VERSION 5.8 ;
BUSBITCHARS "[]" ;
DIVIDERCHAR "/" ;
UNITS
    DATABASE MICRONS 1000 ;
END UNITS

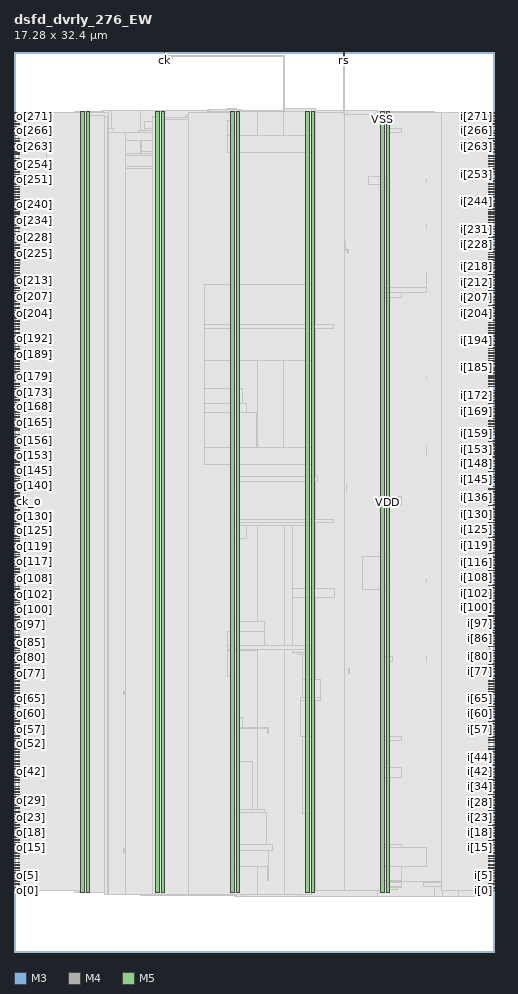
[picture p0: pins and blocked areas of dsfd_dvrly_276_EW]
MACRO dsfd_dvrly_276_EW
  FOREIGN dsfd_dvrly_276_EW 0 0 ;
  CLASS BLOCK ;
  SIZE 17.28 BY 32.4 ;
  PIN ck
    DIRECTION INPUT ;
    USE SIGNAL ;
    PORT
      LAYER M3 ;
        RECT  5.4 32.256 5.418 32.4 ;
    END
  END ck
  PIN ck_o
    DIRECTION OUTPUT ;
    USE SIGNAL ;
    PORT
      LAYER M4 ;
        RECT  0 16.224 0.192 16.248 ;
    END
  END ck_o
  PIN i[0]
    DIRECTION INPUT ;
    USE SIGNAL ;
    PORT
      LAYER M4 ;
        RECT  17.088 2.208 17.28 2.232 ;
    END
  END i[0]
  PIN i[100]
    DIRECTION INPUT ;
    USE SIGNAL ;
    PORT
      LAYER M4 ;
        RECT  17.088 12.384 17.28 12.408 ;
    END
  END i[100]
  PIN i[101]
    DIRECTION INPUT ;
    USE SIGNAL ;
    PORT
      LAYER M4 ;
        RECT  17.088 12.48 17.28 12.504 ;
    END
  END i[101]
  PIN i[102]
    DIRECTION INPUT ;
    USE SIGNAL ;
    PORT
      LAYER M4 ;
        RECT  17.088 12.624 17.28 12.648 ;
    END
  END i[102]
  PIN i[103]
    DIRECTION INPUT ;
    USE SIGNAL ;
    PORT
      LAYER M4 ;
        RECT  17.088 12.72 17.28 12.744 ;
    END
  END i[103]
  PIN i[104]
    DIRECTION INPUT ;
    USE SIGNAL ;
    PORT
      LAYER M4 ;
        RECT  17.088 12.816 17.28 12.84 ;
    END
  END i[104]
  PIN i[105]
    DIRECTION INPUT ;
    USE SIGNAL ;
    PORT
      LAYER M4 ;
        RECT  17.088 12.912 17.28 12.936 ;
    END
  END i[105]
  PIN i[106]
    DIRECTION INPUT ;
    USE SIGNAL ;
    PORT
      LAYER M4 ;
        RECT  17.088 13.008 17.28 13.032 ;
    END
  END i[106]
  PIN i[107]
    DIRECTION INPUT ;
    USE SIGNAL ;
    PORT
      LAYER M4 ;
        RECT  17.088 13.104 17.28 13.128 ;
    END
  END i[107]
  PIN i[108]
    DIRECTION INPUT ;
    USE SIGNAL ;
    PORT
      LAYER M4 ;
        RECT  17.088 13.2 17.28 13.224 ;
    END
  END i[108]
  PIN i[109]
    DIRECTION INPUT ;
    USE SIGNAL ;
    PORT
      LAYER M4 ;
        RECT  17.088 13.296 17.28 13.32 ;
    END
  END i[109]
  PIN i[10]
    DIRECTION INPUT ;
    USE SIGNAL ;
    PORT
      LAYER M4 ;
        RECT  17.088 3.264 17.28 3.288 ;
    END
  END i[10]
  PIN i[110]
    DIRECTION INPUT ;
    USE SIGNAL ;
    PORT
      LAYER M4 ;
        RECT  17.088 13.392 17.28 13.416 ;
    END
  END i[110]
  PIN i[111]
    DIRECTION INPUT ;
    USE SIGNAL ;
    PORT
      LAYER M4 ;
        RECT  17.088 13.536 17.28 13.56 ;
    END
  END i[111]
  PIN i[112]
    DIRECTION INPUT ;
    USE SIGNAL ;
    PORT
      LAYER M4 ;
        RECT  17.088 13.632 17.28 13.656 ;
    END
  END i[112]
  PIN i[113]
    DIRECTION INPUT ;
    USE SIGNAL ;
    PORT
      LAYER M4 ;
        RECT  17.088 13.728 17.28 13.752 ;
    END
  END i[113]
  PIN i[114]
    DIRECTION INPUT ;
    USE SIGNAL ;
    PORT
      LAYER M4 ;
        RECT  17.088 13.824 17.28 13.848 ;
    END
  END i[114]
  PIN i[115]
    DIRECTION INPUT ;
    USE SIGNAL ;
    PORT
      LAYER M4 ;
        RECT  17.088 13.92 17.28 13.944 ;
    END
  END i[115]
  PIN i[116]
    DIRECTION INPUT ;
    USE SIGNAL ;
    PORT
      LAYER M4 ;
        RECT  17.088 14.016 17.28 14.04 ;
    END
  END i[116]
  PIN i[117]
    DIRECTION INPUT ;
    USE SIGNAL ;
    PORT
      LAYER M4 ;
        RECT  17.088 14.112 17.28 14.136 ;
    END
  END i[117]
  PIN i[118]
    DIRECTION INPUT ;
    USE SIGNAL ;
    PORT
      LAYER M4 ;
        RECT  17.088 14.208 17.28 14.232 ;
    END
  END i[118]
  PIN i[119]
    DIRECTION INPUT ;
    USE SIGNAL ;
    PORT
      LAYER M4 ;
        RECT  17.088 14.352 17.28 14.376 ;
    END
  END i[119]
  PIN i[11]
    DIRECTION INPUT ;
    USE SIGNAL ;
    PORT
      LAYER M4 ;
        RECT  17.088 3.36 17.28 3.384 ;
    END
  END i[11]
  PIN i[120]
    DIRECTION INPUT ;
    USE SIGNAL ;
    PORT
      LAYER M4 ;
        RECT  17.088 14.448 17.28 14.472 ;
    END
  END i[120]
  PIN i[121]
    DIRECTION INPUT ;
    USE SIGNAL ;
    PORT
      LAYER M4 ;
        RECT  17.088 14.544 17.28 14.568 ;
    END
  END i[121]
  PIN i[122]
    DIRECTION INPUT ;
    USE SIGNAL ;
    PORT
      LAYER M4 ;
        RECT  17.088 14.64 17.28 14.664 ;
    END
  END i[122]
  PIN i[123]
    DIRECTION INPUT ;
    USE SIGNAL ;
    PORT
      LAYER M4 ;
        RECT  17.088 14.736 17.28 14.76 ;
    END
  END i[123]
  PIN i[124]
    DIRECTION INPUT ;
    USE SIGNAL ;
    PORT
      LAYER M4 ;
        RECT  17.088 14.832 17.28 14.856 ;
    END
  END i[124]
  PIN i[125]
    DIRECTION INPUT ;
    USE SIGNAL ;
    PORT
      LAYER M4 ;
        RECT  17.088 14.928 17.28 14.952 ;
    END
  END i[125]
  PIN i[126]
    DIRECTION INPUT ;
    USE SIGNAL ;
    PORT
      LAYER M4 ;
        RECT  17.088 15.024 17.28 15.048 ;
    END
  END i[126]
  PIN i[127]
    DIRECTION INPUT ;
    USE SIGNAL ;
    PORT
      LAYER M4 ;
        RECT  17.088 15.12 17.28 15.144 ;
    END
  END i[127]
  PIN i[128]
    DIRECTION INPUT ;
    USE SIGNAL ;
    PORT
      LAYER M4 ;
        RECT  17.088 15.264 17.28 15.288 ;
    END
  END i[128]
  PIN i[129]
    DIRECTION INPUT ;
    USE SIGNAL ;
    PORT
      LAYER M4 ;
        RECT  17.088 15.36 17.28 15.384 ;
    END
  END i[129]
  PIN i[12]
    DIRECTION INPUT ;
    USE SIGNAL ;
    PORT
      LAYER M4 ;
        RECT  17.088 3.456 17.28 3.48 ;
    END
  END i[12]
  PIN i[130]
    DIRECTION INPUT ;
    USE SIGNAL ;
    PORT
      LAYER M4 ;
        RECT  17.088 15.456 17.28 15.48 ;
    END
  END i[130]
  PIN i[131]
    DIRECTION INPUT ;
    USE SIGNAL ;
    PORT
      LAYER M4 ;
        RECT  17.088 15.552 17.28 15.576 ;
    END
  END i[131]
  PIN i[132]
    DIRECTION INPUT ;
    USE SIGNAL ;
    PORT
      LAYER M4 ;
        RECT  17.088 15.648 17.28 15.672 ;
    END
  END i[132]
  PIN i[133]
    DIRECTION INPUT ;
    USE SIGNAL ;
    PORT
      LAYER M4 ;
        RECT  17.088 15.744 17.28 15.768 ;
    END
  END i[133]
  PIN i[134]
    DIRECTION INPUT ;
    USE SIGNAL ;
    PORT
      LAYER M4 ;
        RECT  17.088 15.84 17.28 15.864 ;
    END
  END i[134]
  PIN i[135]
    DIRECTION INPUT ;
    USE SIGNAL ;
    PORT
      LAYER M4 ;
        RECT  17.088 15.936 17.28 15.96 ;
    END
  END i[135]
  PIN i[136]
    DIRECTION INPUT ;
    USE SIGNAL ;
    PORT
      LAYER M4 ;
        RECT  17.088 16.08 17.28 16.104 ;
    END
  END i[136]
  PIN i[137]
    DIRECTION INPUT ;
    USE SIGNAL ;
    PORT
      LAYER M4 ;
        RECT  17.088 16.176 17.28 16.2 ;
    END
  END i[137]
  PIN i[138]
    DIRECTION INPUT ;
    USE SIGNAL ;
    PORT
      LAYER M4 ;
        RECT  17.088 16.272 17.28 16.296 ;
    END
  END i[138]
  PIN i[139]
    DIRECTION INPUT ;
    USE SIGNAL ;
    PORT
      LAYER M4 ;
        RECT  17.088 16.368 17.28 16.392 ;
    END
  END i[139]
  PIN i[13]
    DIRECTION INPUT ;
    USE SIGNAL ;
    PORT
      LAYER M4 ;
        RECT  17.088 3.552 17.28 3.576 ;
    END
  END i[13]
  PIN i[140]
    DIRECTION INPUT ;
    USE SIGNAL ;
    PORT
      LAYER M4 ;
        RECT  17.088 16.464 17.28 16.488 ;
    END
  END i[140]
  PIN i[141]
    DIRECTION INPUT ;
    USE SIGNAL ;
    PORT
      LAYER M4 ;
        RECT  17.088 16.56 17.28 16.584 ;
    END
  END i[141]
  PIN i[142]
    DIRECTION INPUT ;
    USE SIGNAL ;
    PORT
      LAYER M4 ;
        RECT  17.088 16.656 17.28 16.68 ;
    END
  END i[142]
  PIN i[143]
    DIRECTION INPUT ;
    USE SIGNAL ;
    PORT
      LAYER M4 ;
        RECT  17.088 16.752 17.28 16.776 ;
    END
  END i[143]
  PIN i[144]
    DIRECTION INPUT ;
    USE SIGNAL ;
    PORT
      LAYER M4 ;
        RECT  17.088 16.896 17.28 16.92 ;
    END
  END i[144]
  PIN i[145]
    DIRECTION INPUT ;
    USE SIGNAL ;
    PORT
      LAYER M4 ;
        RECT  17.088 16.992 17.28 17.016 ;
    END
  END i[145]
  PIN i[146]
    DIRECTION INPUT ;
    USE SIGNAL ;
    PORT
      LAYER M4 ;
        RECT  17.088 17.088 17.28 17.112 ;
    END
  END i[146]
  PIN i[147]
    DIRECTION INPUT ;
    USE SIGNAL ;
    PORT
      LAYER M4 ;
        RECT  17.088 17.184 17.28 17.208 ;
    END
  END i[147]
  PIN i[148]
    DIRECTION INPUT ;
    USE SIGNAL ;
    PORT
      LAYER M4 ;
        RECT  17.088 17.28 17.28 17.304 ;
    END
  END i[148]
  PIN i[149]
    DIRECTION INPUT ;
    USE SIGNAL ;
    PORT
      LAYER M4 ;
        RECT  17.088 17.376 17.28 17.4 ;
    END
  END i[149]
  PIN i[14]
    DIRECTION INPUT ;
    USE SIGNAL ;
    PORT
      LAYER M4 ;
        RECT  17.088 3.648 17.28 3.672 ;
    END
  END i[14]
  PIN i[150]
    DIRECTION INPUT ;
    USE SIGNAL ;
    PORT
      LAYER M4 ;
        RECT  17.088 17.472 17.28 17.496 ;
    END
  END i[150]
  PIN i[151]
    DIRECTION INPUT ;
    USE SIGNAL ;
    PORT
      LAYER M4 ;
        RECT  17.088 17.568 17.28 17.592 ;
    END
  END i[151]
  PIN i[152]
    DIRECTION INPUT ;
    USE SIGNAL ;
    PORT
      LAYER M4 ;
        RECT  17.088 17.664 17.28 17.688 ;
    END
  END i[152]
  PIN i[153]
    DIRECTION INPUT ;
    USE SIGNAL ;
    PORT
      LAYER M4 ;
        RECT  17.088 17.808 17.28 17.832 ;
    END
  END i[153]
  PIN i[154]
    DIRECTION INPUT ;
    USE SIGNAL ;
    PORT
      LAYER M4 ;
        RECT  17.088 17.904 17.28 17.928 ;
    END
  END i[154]
  PIN i[155]
    DIRECTION INPUT ;
    USE SIGNAL ;
    PORT
      LAYER M4 ;
        RECT  17.088 18 17.28 18.024 ;
    END
  END i[155]
  PIN i[156]
    DIRECTION INPUT ;
    USE SIGNAL ;
    PORT
      LAYER M4 ;
        RECT  17.088 18.096 17.28 18.12 ;
    END
  END i[156]
  PIN i[157]
    DIRECTION INPUT ;
    USE SIGNAL ;
    PORT
      LAYER M4 ;
        RECT  17.088 18.192 17.28 18.216 ;
    END
  END i[157]
  PIN i[158]
    DIRECTION INPUT ;
    USE SIGNAL ;
    PORT
      LAYER M4 ;
        RECT  17.088 18.288 17.28 18.312 ;
    END
  END i[158]
  PIN i[159]
    DIRECTION INPUT ;
    USE SIGNAL ;
    PORT
      LAYER M4 ;
        RECT  17.088 18.384 17.28 18.408 ;
    END
  END i[159]
  PIN i[15]
    DIRECTION INPUT ;
    USE SIGNAL ;
    PORT
      LAYER M4 ;
        RECT  17.088 3.744 17.28 3.768 ;
    END
  END i[15]
  PIN i[160]
    DIRECTION INPUT ;
    USE SIGNAL ;
    PORT
      LAYER M4 ;
        RECT  17.088 18.48 17.28 18.504 ;
    END
  END i[160]
  PIN i[161]
    DIRECTION INPUT ;
    USE SIGNAL ;
    PORT
      LAYER M4 ;
        RECT  17.088 18.624 17.28 18.648 ;
    END
  END i[161]
  PIN i[162]
    DIRECTION INPUT ;
    USE SIGNAL ;
    PORT
      LAYER M4 ;
        RECT  17.088 18.72 17.28 18.744 ;
    END
  END i[162]
  PIN i[163]
    DIRECTION INPUT ;
    USE SIGNAL ;
    PORT
      LAYER M4 ;
        RECT  17.088 18.816 17.28 18.84 ;
    END
  END i[163]
  PIN i[164]
    DIRECTION INPUT ;
    USE SIGNAL ;
    PORT
      LAYER M4 ;
        RECT  17.088 18.912 17.28 18.936 ;
    END
  END i[164]
  PIN i[165]
    DIRECTION INPUT ;
    USE SIGNAL ;
    PORT
      LAYER M4 ;
        RECT  17.088 19.008 17.28 19.032 ;
    END
  END i[165]
  PIN i[166]
    DIRECTION INPUT ;
    USE SIGNAL ;
    PORT
      LAYER M4 ;
        RECT  17.088 19.104 17.28 19.128 ;
    END
  END i[166]
  PIN i[167]
    DIRECTION INPUT ;
    USE SIGNAL ;
    PORT
      LAYER M4 ;
        RECT  17.088 19.2 17.28 19.224 ;
    END
  END i[167]
  PIN i[168]
    DIRECTION INPUT ;
    USE SIGNAL ;
    PORT
      LAYER M4 ;
        RECT  17.088 19.296 17.28 19.32 ;
    END
  END i[168]
  PIN i[169]
    DIRECTION INPUT ;
    USE SIGNAL ;
    PORT
      LAYER M4 ;
        RECT  17.088 19.44 17.28 19.464 ;
    END
  END i[169]
  PIN i[16]
    DIRECTION INPUT ;
    USE SIGNAL ;
    PORT
      LAYER M4 ;
        RECT  17.088 3.84 17.28 3.864 ;
    END
  END i[16]
  PIN i[170]
    DIRECTION INPUT ;
    USE SIGNAL ;
    PORT
      LAYER M4 ;
        RECT  17.088 19.536 17.28 19.56 ;
    END
  END i[170]
  PIN i[171]
    DIRECTION INPUT ;
    USE SIGNAL ;
    PORT
      LAYER M4 ;
        RECT  17.088 19.632 17.28 19.656 ;
    END
  END i[171]
  PIN i[172]
    DIRECTION INPUT ;
    USE SIGNAL ;
    PORT
      LAYER M4 ;
        RECT  17.088 19.728 17.28 19.752 ;
    END
  END i[172]
  PIN i[173]
    DIRECTION INPUT ;
    USE SIGNAL ;
    PORT
      LAYER M4 ;
        RECT  17.088 19.824 17.28 19.848 ;
    END
  END i[173]
  PIN i[174]
    DIRECTION INPUT ;
    USE SIGNAL ;
    PORT
      LAYER M4 ;
        RECT  17.088 19.92 17.28 19.944 ;
    END
  END i[174]
  PIN i[175]
    DIRECTION INPUT ;
    USE SIGNAL ;
    PORT
      LAYER M4 ;
        RECT  17.088 20.016 17.28 20.04 ;
    END
  END i[175]
  PIN i[176]
    DIRECTION INPUT ;
    USE SIGNAL ;
    PORT
      LAYER M4 ;
        RECT  17.088 20.112 17.28 20.136 ;
    END
  END i[176]
  PIN i[177]
    DIRECTION INPUT ;
    USE SIGNAL ;
    PORT
      LAYER M4 ;
        RECT  17.088 20.208 17.28 20.232 ;
    END
  END i[177]
  PIN i[178]
    DIRECTION INPUT ;
    USE SIGNAL ;
    PORT
      LAYER M4 ;
        RECT  17.088 20.352 17.28 20.376 ;
    END
  END i[178]
  PIN i[179]
    DIRECTION INPUT ;
    USE SIGNAL ;
    PORT
      LAYER M4 ;
        RECT  17.088 20.448 17.28 20.472 ;
    END
  END i[179]
  PIN i[17]
    DIRECTION INPUT ;
    USE SIGNAL ;
    PORT
      LAYER M4 ;
        RECT  17.088 3.936 17.28 3.96 ;
    END
  END i[17]
  PIN i[180]
    DIRECTION INPUT ;
    USE SIGNAL ;
    PORT
      LAYER M4 ;
        RECT  17.088 20.544 17.28 20.568 ;
    END
  END i[180]
  PIN i[181]
    DIRECTION INPUT ;
    USE SIGNAL ;
    PORT
      LAYER M4 ;
        RECT  17.088 20.64 17.28 20.664 ;
    END
  END i[181]
  PIN i[182]
    DIRECTION INPUT ;
    USE SIGNAL ;
    PORT
      LAYER M4 ;
        RECT  17.088 20.736 17.28 20.76 ;
    END
  END i[182]
  PIN i[183]
    DIRECTION INPUT ;
    USE SIGNAL ;
    PORT
      LAYER M4 ;
        RECT  17.088 20.832 17.28 20.856 ;
    END
  END i[183]
  PIN i[184]
    DIRECTION INPUT ;
    USE SIGNAL ;
    PORT
      LAYER M4 ;
        RECT  17.088 20.928 17.28 20.952 ;
    END
  END i[184]
  PIN i[185]
    DIRECTION INPUT ;
    USE SIGNAL ;
    PORT
      LAYER M4 ;
        RECT  17.088 21.024 17.28 21.048 ;
    END
  END i[185]
  PIN i[186]
    DIRECTION INPUT ;
    USE SIGNAL ;
    PORT
      LAYER M4 ;
        RECT  17.088 21.168 17.28 21.192 ;
    END
  END i[186]
  PIN i[187]
    DIRECTION INPUT ;
    USE SIGNAL ;
    PORT
      LAYER M4 ;
        RECT  17.088 21.264 17.28 21.288 ;
    END
  END i[187]
  PIN i[188]
    DIRECTION INPUT ;
    USE SIGNAL ;
    PORT
      LAYER M4 ;
        RECT  17.088 21.36 17.28 21.384 ;
    END
  END i[188]
  PIN i[189]
    DIRECTION INPUT ;
    USE SIGNAL ;
    PORT
      LAYER M4 ;
        RECT  17.088 21.456 17.28 21.48 ;
    END
  END i[189]
  PIN i[18]
    DIRECTION INPUT ;
    USE SIGNAL ;
    PORT
      LAYER M4 ;
        RECT  17.088 4.032 17.28 4.056 ;
    END
  END i[18]
  PIN i[190]
    DIRECTION INPUT ;
    USE SIGNAL ;
    PORT
      LAYER M4 ;
        RECT  17.088 21.552 17.28 21.576 ;
    END
  END i[190]
  PIN i[191]
    DIRECTION INPUT ;
    USE SIGNAL ;
    PORT
      LAYER M4 ;
        RECT  17.088 21.648 17.28 21.672 ;
    END
  END i[191]
  PIN i[192]
    DIRECTION INPUT ;
    USE SIGNAL ;
    PORT
      LAYER M4 ;
        RECT  17.088 21.744 17.28 21.768 ;
    END
  END i[192]
  PIN i[193]
    DIRECTION INPUT ;
    USE SIGNAL ;
    PORT
      LAYER M4 ;
        RECT  17.088 21.84 17.28 21.864 ;
    END
  END i[193]
  PIN i[194]
    DIRECTION INPUT ;
    USE SIGNAL ;
    PORT
      LAYER M4 ;
        RECT  17.088 21.984 17.28 22.008 ;
    END
  END i[194]
  PIN i[195]
    DIRECTION INPUT ;
    USE SIGNAL ;
    PORT
      LAYER M4 ;
        RECT  17.088 22.08 17.28 22.104 ;
    END
  END i[195]
  PIN i[196]
    DIRECTION INPUT ;
    USE SIGNAL ;
    PORT
      LAYER M4 ;
        RECT  17.088 22.176 17.28 22.2 ;
    END
  END i[196]
  PIN i[197]
    DIRECTION INPUT ;
    USE SIGNAL ;
    PORT
      LAYER M4 ;
        RECT  17.088 22.272 17.28 22.296 ;
    END
  END i[197]
  PIN i[198]
    DIRECTION INPUT ;
    USE SIGNAL ;
    PORT
      LAYER M4 ;
        RECT  17.088 22.368 17.28 22.392 ;
    END
  END i[198]
  PIN i[199]
    DIRECTION INPUT ;
    USE SIGNAL ;
    PORT
      LAYER M4 ;
        RECT  17.088 22.464 17.28 22.488 ;
    END
  END i[199]
  PIN i[19]
    DIRECTION INPUT ;
    USE SIGNAL ;
    PORT
      LAYER M4 ;
        RECT  17.088 4.176 17.28 4.2 ;
    END
  END i[19]
  PIN i[1]
    DIRECTION INPUT ;
    USE SIGNAL ;
    PORT
      LAYER M4 ;
        RECT  17.088 2.304 17.28 2.328 ;
    END
  END i[1]
  PIN i[200]
    DIRECTION INPUT ;
    USE SIGNAL ;
    PORT
      LAYER M4 ;
        RECT  17.088 22.56 17.28 22.584 ;
    END
  END i[200]
  PIN i[201]
    DIRECTION INPUT ;
    USE SIGNAL ;
    PORT
      LAYER M4 ;
        RECT  17.088 22.656 17.28 22.68 ;
    END
  END i[201]
  PIN i[202]
    DIRECTION INPUT ;
    USE SIGNAL ;
    PORT
      LAYER M4 ;
        RECT  17.088 22.752 17.28 22.776 ;
    END
  END i[202]
  PIN i[203]
    DIRECTION INPUT ;
    USE SIGNAL ;
    PORT
      LAYER M4 ;
        RECT  17.088 22.896 17.28 22.92 ;
    END
  END i[203]
  PIN i[204]
    DIRECTION INPUT ;
    USE SIGNAL ;
    PORT
      LAYER M4 ;
        RECT  17.088 22.992 17.28 23.016 ;
    END
  END i[204]
  PIN i[205]
    DIRECTION INPUT ;
    USE SIGNAL ;
    PORT
      LAYER M4 ;
        RECT  17.088 23.088 17.28 23.112 ;
    END
  END i[205]
  PIN i[206]
    DIRECTION INPUT ;
    USE SIGNAL ;
    PORT
      LAYER M4 ;
        RECT  17.088 23.184 17.28 23.208 ;
    END
  END i[206]
  PIN i[207]
    DIRECTION INPUT ;
    USE SIGNAL ;
    PORT
      LAYER M4 ;
        RECT  17.088 23.28 17.28 23.304 ;
    END
  END i[207]
  PIN i[208]
    DIRECTION INPUT ;
    USE SIGNAL ;
    PORT
      LAYER M4 ;
        RECT  17.088 23.376 17.28 23.4 ;
    END
  END i[208]
  PIN i[209]
    DIRECTION INPUT ;
    USE SIGNAL ;
    PORT
      LAYER M4 ;
        RECT  17.088 23.472 17.28 23.496 ;
    END
  END i[209]
  PIN i[20]
    DIRECTION INPUT ;
    USE SIGNAL ;
    PORT
      LAYER M4 ;
        RECT  17.088 4.272 17.28 4.296 ;
    END
  END i[20]
  PIN i[210]
    DIRECTION INPUT ;
    USE SIGNAL ;
    PORT
      LAYER M4 ;
        RECT  17.088 23.568 17.28 23.592 ;
    END
  END i[210]
  PIN i[211]
    DIRECTION INPUT ;
    USE SIGNAL ;
    PORT
      LAYER M4 ;
        RECT  17.088 23.712 17.28 23.736 ;
    END
  END i[211]
  PIN i[212]
    DIRECTION INPUT ;
    USE SIGNAL ;
    PORT
      LAYER M4 ;
        RECT  17.088 23.808 17.28 23.832 ;
    END
  END i[212]
  PIN i[213]
    DIRECTION INPUT ;
    USE SIGNAL ;
    PORT
      LAYER M4 ;
        RECT  17.088 23.904 17.28 23.928 ;
    END
  END i[213]
  PIN i[214]
    DIRECTION INPUT ;
    USE SIGNAL ;
    PORT
      LAYER M4 ;
        RECT  17.088 24 17.28 24.024 ;
    END
  END i[214]
  PIN i[215]
    DIRECTION INPUT ;
    USE SIGNAL ;
    PORT
      LAYER M4 ;
        RECT  17.088 24.096 17.28 24.12 ;
    END
  END i[215]
  PIN i[216]
    DIRECTION INPUT ;
    USE SIGNAL ;
    PORT
      LAYER M4 ;
        RECT  17.088 24.192 17.28 24.216 ;
    END
  END i[216]
  PIN i[217]
    DIRECTION INPUT ;
    USE SIGNAL ;
    PORT
      LAYER M4 ;
        RECT  17.088 24.288 17.28 24.312 ;
    END
  END i[217]
  PIN i[218]
    DIRECTION INPUT ;
    USE SIGNAL ;
    PORT
      LAYER M4 ;
        RECT  17.088 24.384 17.28 24.408 ;
    END
  END i[218]
  PIN i[219]
    DIRECTION INPUT ;
    USE SIGNAL ;
    PORT
      LAYER M4 ;
        RECT  17.088 24.48 17.28 24.504 ;
    END
  END i[219]
  PIN i[21]
    DIRECTION INPUT ;
    USE SIGNAL ;
    PORT
      LAYER M4 ;
        RECT  17.088 4.368 17.28 4.392 ;
    END
  END i[21]
  PIN i[220]
    DIRECTION INPUT ;
    USE SIGNAL ;
    PORT
      LAYER M4 ;
        RECT  17.088 24.624 17.28 24.648 ;
    END
  END i[220]
  PIN i[221]
    DIRECTION INPUT ;
    USE SIGNAL ;
    PORT
      LAYER M4 ;
        RECT  17.088 24.72 17.28 24.744 ;
    END
  END i[221]
  PIN i[222]
    DIRECTION INPUT ;
    USE SIGNAL ;
    PORT
      LAYER M4 ;
        RECT  17.088 24.816 17.28 24.84 ;
    END
  END i[222]
  PIN i[223]
    DIRECTION INPUT ;
    USE SIGNAL ;
    PORT
      LAYER M4 ;
        RECT  17.088 24.912 17.28 24.936 ;
    END
  END i[223]
  PIN i[224]
    DIRECTION INPUT ;
    USE SIGNAL ;
    PORT
      LAYER M4 ;
        RECT  17.088 25.008 17.28 25.032 ;
    END
  END i[224]
  PIN i[225]
    DIRECTION INPUT ;
    USE SIGNAL ;
    PORT
      LAYER M4 ;
        RECT  17.088 25.104 17.28 25.128 ;
    END
  END i[225]
  PIN i[226]
    DIRECTION INPUT ;
    USE SIGNAL ;
    PORT
      LAYER M4 ;
        RECT  17.088 25.2 17.28 25.224 ;
    END
  END i[226]
  PIN i[227]
    DIRECTION INPUT ;
    USE SIGNAL ;
    PORT
      LAYER M4 ;
        RECT  17.088 25.296 17.28 25.32 ;
    END
  END i[227]
  PIN i[228]
    DIRECTION INPUT ;
    USE SIGNAL ;
    PORT
      LAYER M4 ;
        RECT  17.088 25.44 17.28 25.464 ;
    END
  END i[228]
  PIN i[229]
    DIRECTION INPUT ;
    USE SIGNAL ;
    PORT
      LAYER M4 ;
        RECT  17.088 25.536 17.28 25.56 ;
    END
  END i[229]
  PIN i[22]
    DIRECTION INPUT ;
    USE SIGNAL ;
    PORT
      LAYER M4 ;
        RECT  17.088 4.464 17.28 4.488 ;
    END
  END i[22]
  PIN i[230]
    DIRECTION INPUT ;
    USE SIGNAL ;
    PORT
      LAYER M4 ;
        RECT  17.088 25.632 17.28 25.656 ;
    END
  END i[230]
  PIN i[231]
    DIRECTION INPUT ;
    USE SIGNAL ;
    PORT
      LAYER M4 ;
        RECT  17.088 25.728 17.28 25.752 ;
    END
  END i[231]
  PIN i[232]
    DIRECTION INPUT ;
    USE SIGNAL ;
    PORT
      LAYER M4 ;
        RECT  17.088 25.824 17.28 25.848 ;
    END
  END i[232]
  PIN i[233]
    DIRECTION INPUT ;
    USE SIGNAL ;
    PORT
      LAYER M4 ;
        RECT  17.088 25.92 17.28 25.944 ;
    END
  END i[233]
  PIN i[234]
    DIRECTION INPUT ;
    USE SIGNAL ;
    PORT
      LAYER M4 ;
        RECT  17.088 26.016 17.28 26.04 ;
    END
  END i[234]
  PIN i[235]
    DIRECTION INPUT ;
    USE SIGNAL ;
    PORT
      LAYER M4 ;
        RECT  17.088 26.112 17.28 26.136 ;
    END
  END i[235]
  PIN i[236]
    DIRECTION INPUT ;
    USE SIGNAL ;
    PORT
      LAYER M4 ;
        RECT  17.088 26.256 17.28 26.28 ;
    END
  END i[236]
  PIN i[237]
    DIRECTION INPUT ;
    USE SIGNAL ;
    PORT
      LAYER M4 ;
        RECT  17.088 26.352 17.28 26.376 ;
    END
  END i[237]
  PIN i[238]
    DIRECTION INPUT ;
    USE SIGNAL ;
    PORT
      LAYER M4 ;
        RECT  17.088 26.448 17.28 26.472 ;
    END
  END i[238]
  PIN i[239]
    DIRECTION INPUT ;
    USE SIGNAL ;
    PORT
      LAYER M4 ;
        RECT  17.088 26.544 17.28 26.568 ;
    END
  END i[239]
  PIN i[23]
    DIRECTION INPUT ;
    USE SIGNAL ;
    PORT
      LAYER M4 ;
        RECT  17.088 4.56 17.28 4.584 ;
    END
  END i[23]
  PIN i[240]
    DIRECTION INPUT ;
    USE SIGNAL ;
    PORT
      LAYER M4 ;
        RECT  17.088 26.64 17.28 26.664 ;
    END
  END i[240]
  PIN i[241]
    DIRECTION INPUT ;
    USE SIGNAL ;
    PORT
      LAYER M4 ;
        RECT  17.088 26.736 17.28 26.76 ;
    END
  END i[241]
  PIN i[242]
    DIRECTION INPUT ;
    USE SIGNAL ;
    PORT
      LAYER M4 ;
        RECT  17.088 26.832 17.28 26.856 ;
    END
  END i[242]
  PIN i[243]
    DIRECTION INPUT ;
    USE SIGNAL ;
    PORT
      LAYER M4 ;
        RECT  17.088 26.928 17.28 26.952 ;
    END
  END i[243]
  PIN i[244]
    DIRECTION INPUT ;
    USE SIGNAL ;
    PORT
      LAYER M4 ;
        RECT  17.088 27.024 17.28 27.048 ;
    END
  END i[244]
  PIN i[245]
    DIRECTION INPUT ;
    USE SIGNAL ;
    PORT
      LAYER M4 ;
        RECT  17.088 27.168 17.28 27.192 ;
    END
  END i[245]
  PIN i[246]
    DIRECTION INPUT ;
    USE SIGNAL ;
    PORT
      LAYER M4 ;
        RECT  17.088 27.264 17.28 27.288 ;
    END
  END i[246]
  PIN i[247]
    DIRECTION INPUT ;
    USE SIGNAL ;
    PORT
      LAYER M4 ;
        RECT  17.088 27.36 17.28 27.384 ;
    END
  END i[247]
  PIN i[248]
    DIRECTION INPUT ;
    USE SIGNAL ;
    PORT
      LAYER M4 ;
        RECT  17.088 27.456 17.28 27.48 ;
    END
  END i[248]
  PIN i[249]
    DIRECTION INPUT ;
    USE SIGNAL ;
    PORT
      LAYER M4 ;
        RECT  17.088 27.552 17.28 27.576 ;
    END
  END i[249]
  PIN i[24]
    DIRECTION INPUT ;
    USE SIGNAL ;
    PORT
      LAYER M4 ;
        RECT  17.088 4.656 17.28 4.68 ;
    END
  END i[24]
  PIN i[250]
    DIRECTION INPUT ;
    USE SIGNAL ;
    PORT
      LAYER M4 ;
        RECT  17.088 27.648 17.28 27.672 ;
    END
  END i[250]
  PIN i[251]
    DIRECTION INPUT ;
    USE SIGNAL ;
    PORT
      LAYER M4 ;
        RECT  17.088 27.744 17.28 27.768 ;
    END
  END i[251]
  PIN i[252]
    DIRECTION INPUT ;
    USE SIGNAL ;
    PORT
      LAYER M4 ;
        RECT  17.088 27.84 17.28 27.864 ;
    END
  END i[252]
  PIN i[253]
    DIRECTION INPUT ;
    USE SIGNAL ;
    PORT
      LAYER M4 ;
        RECT  17.088 27.984 17.28 28.008 ;
    END
  END i[253]
  PIN i[254]
    DIRECTION INPUT ;
    USE SIGNAL ;
    PORT
      LAYER M4 ;
        RECT  17.088 28.08 17.28 28.104 ;
    END
  END i[254]
  PIN i[255]
    DIRECTION INPUT ;
    USE SIGNAL ;
    PORT
      LAYER M4 ;
        RECT  17.088 28.176 17.28 28.2 ;
    END
  END i[255]
  PIN i[256]
    DIRECTION INPUT ;
    USE SIGNAL ;
    PORT
      LAYER M4 ;
        RECT  17.088 28.272 17.28 28.296 ;
    END
  END i[256]
  PIN i[257]
    DIRECTION INPUT ;
    USE SIGNAL ;
    PORT
      LAYER M4 ;
        RECT  17.088 28.368 17.28 28.392 ;
    END
  END i[257]
  PIN i[258]
    DIRECTION INPUT ;
    USE SIGNAL ;
    PORT
      LAYER M4 ;
        RECT  17.088 28.464 17.28 28.488 ;
    END
  END i[258]
  PIN i[259]
    DIRECTION INPUT ;
    USE SIGNAL ;
    PORT
      LAYER M4 ;
        RECT  17.088 28.56 17.28 28.584 ;
    END
  END i[259]
  PIN i[25]
    DIRECTION INPUT ;
    USE SIGNAL ;
    PORT
      LAYER M4 ;
        RECT  17.088 4.752 17.28 4.776 ;
    END
  END i[25]
  PIN i[260]
    DIRECTION INPUT ;
    USE SIGNAL ;
    PORT
      LAYER M4 ;
        RECT  17.088 28.656 17.28 28.68 ;
    END
  END i[260]
  PIN i[261]
    DIRECTION INPUT ;
    USE SIGNAL ;
    PORT
      LAYER M4 ;
        RECT  17.088 28.8 17.28 28.824 ;
    END
  END i[261]
  PIN i[262]
    DIRECTION INPUT ;
    USE SIGNAL ;
    PORT
      LAYER M4 ;
        RECT  17.088 28.896 17.28 28.92 ;
    END
  END i[262]
  PIN i[263]
    DIRECTION INPUT ;
    USE SIGNAL ;
    PORT
      LAYER M4 ;
        RECT  17.088 28.992 17.28 29.016 ;
    END
  END i[263]
  PIN i[264]
    DIRECTION INPUT ;
    USE SIGNAL ;
    PORT
      LAYER M4 ;
        RECT  17.088 29.088 17.28 29.112 ;
    END
  END i[264]
  PIN i[265]
    DIRECTION INPUT ;
    USE SIGNAL ;
    PORT
      LAYER M4 ;
        RECT  17.088 29.184 17.28 29.208 ;
    END
  END i[265]
  PIN i[266]
    DIRECTION INPUT ;
    USE SIGNAL ;
    PORT
      LAYER M4 ;
        RECT  17.088 29.28 17.28 29.304 ;
    END
  END i[266]
  PIN i[267]
    DIRECTION INPUT ;
    USE SIGNAL ;
    PORT
      LAYER M4 ;
        RECT  17.088 29.376 17.28 29.4 ;
    END
  END i[267]
  PIN i[268]
    DIRECTION INPUT ;
    USE SIGNAL ;
    PORT
      LAYER M4 ;
        RECT  17.088 29.472 17.28 29.496 ;
    END
  END i[268]
  PIN i[269]
    DIRECTION INPUT ;
    USE SIGNAL ;
    PORT
      LAYER M4 ;
        RECT  17.088 29.568 17.28 29.592 ;
    END
  END i[269]
  PIN i[26]
    DIRECTION INPUT ;
    USE SIGNAL ;
    PORT
      LAYER M4 ;
        RECT  17.088 4.848 17.28 4.872 ;
    END
  END i[26]
  PIN i[270]
    DIRECTION INPUT ;
    USE SIGNAL ;
    PORT
      LAYER M4 ;
        RECT  17.088 29.712 17.28 29.736 ;
    END
  END i[270]
  PIN i[271]
    DIRECTION INPUT ;
    USE SIGNAL ;
    PORT
      LAYER M4 ;
        RECT  17.088 29.808 17.28 29.832 ;
    END
  END i[271]
  PIN i[272]
    DIRECTION INPUT ;
    USE SIGNAL ;
    PORT
      LAYER M4 ;
        RECT  17.088 29.904 17.28 29.928 ;
    END
  END i[272]
  PIN i[273]
    DIRECTION INPUT ;
    USE SIGNAL ;
    PORT
      LAYER M4 ;
        RECT  17.088 30 17.28 30.024 ;
    END
  END i[273]
  PIN i[274]
    DIRECTION INPUT ;
    USE SIGNAL ;
    PORT
      LAYER M4 ;
        RECT  17.088 30.096 17.28 30.12 ;
    END
  END i[274]
  PIN i[275]
    DIRECTION INPUT ;
    USE SIGNAL ;
    PORT
      LAYER M4 ;
        RECT  17.088 30.192 17.28 30.216 ;
    END
  END i[275]
  PIN i[27]
    DIRECTION INPUT ;
    USE SIGNAL ;
    PORT
      LAYER M4 ;
        RECT  17.088 4.992 17.28 5.016 ;
    END
  END i[27]
  PIN i[28]
    DIRECTION INPUT ;
    USE SIGNAL ;
    PORT
      LAYER M4 ;
        RECT  17.088 5.088 17.28 5.112 ;
    END
  END i[28]
  PIN i[29]
    DIRECTION INPUT ;
    USE SIGNAL ;
    PORT
      LAYER M4 ;
        RECT  17.088 5.184 17.28 5.208 ;
    END
  END i[29]
  PIN i[2]
    DIRECTION INPUT ;
    USE SIGNAL ;
    PORT
      LAYER M4 ;
        RECT  17.088 2.448 17.28 2.472 ;
    END
  END i[2]
  PIN i[30]
    DIRECTION INPUT ;
    USE SIGNAL ;
    PORT
      LAYER M4 ;
        RECT  17.088 5.28 17.28 5.304 ;
    END
  END i[30]
  PIN i[31]
    DIRECTION INPUT ;
    USE SIGNAL ;
    PORT
      LAYER M4 ;
        RECT  17.088 5.376 17.28 5.4 ;
    END
  END i[31]
  PIN i[32]
    DIRECTION INPUT ;
    USE SIGNAL ;
    PORT
      LAYER M4 ;
        RECT  17.088 5.472 17.28 5.496 ;
    END
  END i[32]
  PIN i[33]
    DIRECTION INPUT ;
    USE SIGNAL ;
    PORT
      LAYER M4 ;
        RECT  17.088 5.568 17.28 5.592 ;
    END
  END i[33]
  PIN i[34]
    DIRECTION INPUT ;
    USE SIGNAL ;
    PORT
      LAYER M4 ;
        RECT  17.088 5.664 17.28 5.688 ;
    END
  END i[34]
  PIN i[35]
    DIRECTION INPUT ;
    USE SIGNAL ;
    PORT
      LAYER M4 ;
        RECT  17.088 5.76 17.28 5.784 ;
    END
  END i[35]
  PIN i[36]
    DIRECTION INPUT ;
    USE SIGNAL ;
    PORT
      LAYER M4 ;
        RECT  17.088 5.904 17.28 5.928 ;
    END
  END i[36]
  PIN i[37]
    DIRECTION INPUT ;
    USE SIGNAL ;
    PORT
      LAYER M4 ;
        RECT  17.088 6 17.28 6.024 ;
    END
  END i[37]
  PIN i[38]
    DIRECTION INPUT ;
    USE SIGNAL ;
    PORT
      LAYER M4 ;
        RECT  17.088 6.096 17.28 6.12 ;
    END
  END i[38]
  PIN i[39]
    DIRECTION INPUT ;
    USE SIGNAL ;
    PORT
      LAYER M4 ;
        RECT  17.088 6.192 17.28 6.216 ;
    END
  END i[39]
  PIN i[3]
    DIRECTION INPUT ;
    USE SIGNAL ;
    PORT
      LAYER M4 ;
        RECT  17.088 2.544 17.28 2.568 ;
    END
  END i[3]
  PIN i[40]
    DIRECTION INPUT ;
    USE SIGNAL ;
    PORT
      LAYER M4 ;
        RECT  17.088 6.288 17.28 6.312 ;
    END
  END i[40]
  PIN i[41]
    DIRECTION INPUT ;
    USE SIGNAL ;
    PORT
      LAYER M4 ;
        RECT  17.088 6.384 17.28 6.408 ;
    END
  END i[41]
  PIN i[42]
    DIRECTION INPUT ;
    USE SIGNAL ;
    PORT
      LAYER M4 ;
        RECT  17.088 6.48 17.28 6.504 ;
    END
  END i[42]
  PIN i[43]
    DIRECTION INPUT ;
    USE SIGNAL ;
    PORT
      LAYER M4 ;
        RECT  17.088 6.576 17.28 6.6 ;
    END
  END i[43]
  PIN i[44]
    DIRECTION INPUT ;
    USE SIGNAL ;
    PORT
      LAYER M4 ;
        RECT  17.088 6.72 17.28 6.744 ;
    END
  END i[44]
  PIN i[45]
    DIRECTION INPUT ;
    USE SIGNAL ;
    PORT
      LAYER M4 ;
        RECT  17.088 6.816 17.28 6.84 ;
    END
  END i[45]
  PIN i[46]
    DIRECTION INPUT ;
    USE SIGNAL ;
    PORT
      LAYER M4 ;
        RECT  17.088 6.912 17.28 6.936 ;
    END
  END i[46]
  PIN i[47]
    DIRECTION INPUT ;
    USE SIGNAL ;
    PORT
      LAYER M4 ;
        RECT  17.088 7.008 17.28 7.032 ;
    END
  END i[47]
  PIN i[48]
    DIRECTION INPUT ;
    USE SIGNAL ;
    PORT
      LAYER M4 ;
        RECT  17.088 7.104 17.28 7.128 ;
    END
  END i[48]
  PIN i[49]
    DIRECTION INPUT ;
    USE SIGNAL ;
    PORT
      LAYER M4 ;
        RECT  17.088 7.2 17.28 7.224 ;
    END
  END i[49]
  PIN i[4]
    DIRECTION INPUT ;
    USE SIGNAL ;
    PORT
      LAYER M4 ;
        RECT  17.088 2.64 17.28 2.664 ;
    END
  END i[4]
  PIN i[50]
    DIRECTION INPUT ;
    USE SIGNAL ;
    PORT
      LAYER M4 ;
        RECT  17.088 7.296 17.28 7.32 ;
    END
  END i[50]
  PIN i[51]
    DIRECTION INPUT ;
    USE SIGNAL ;
    PORT
      LAYER M4 ;
        RECT  17.088 7.392 17.28 7.416 ;
    END
  END i[51]
  PIN i[52]
    DIRECTION INPUT ;
    USE SIGNAL ;
    PORT
      LAYER M4 ;
        RECT  17.088 7.536 17.28 7.56 ;
    END
  END i[52]
  PIN i[53]
    DIRECTION INPUT ;
    USE SIGNAL ;
    PORT
      LAYER M4 ;
        RECT  17.088 7.632 17.28 7.656 ;
    END
  END i[53]
  PIN i[54]
    DIRECTION INPUT ;
    USE SIGNAL ;
    PORT
      LAYER M4 ;
        RECT  17.088 7.728 17.28 7.752 ;
    END
  END i[54]
  PIN i[55]
    DIRECTION INPUT ;
    USE SIGNAL ;
    PORT
      LAYER M4 ;
        RECT  17.088 7.824 17.28 7.848 ;
    END
  END i[55]
  PIN i[56]
    DIRECTION INPUT ;
    USE SIGNAL ;
    PORT
      LAYER M4 ;
        RECT  17.088 7.92 17.28 7.944 ;
    END
  END i[56]
  PIN i[57]
    DIRECTION INPUT ;
    USE SIGNAL ;
    PORT
      LAYER M4 ;
        RECT  17.088 8.016 17.28 8.04 ;
    END
  END i[57]
  PIN i[58]
    DIRECTION INPUT ;
    USE SIGNAL ;
    PORT
      LAYER M4 ;
        RECT  17.088 8.112 17.28 8.136 ;
    END
  END i[58]
  PIN i[59]
    DIRECTION INPUT ;
    USE SIGNAL ;
    PORT
      LAYER M4 ;
        RECT  17.088 8.208 17.28 8.232 ;
    END
  END i[59]
  PIN i[5]
    DIRECTION INPUT ;
    USE SIGNAL ;
    PORT
      LAYER M4 ;
        RECT  17.088 2.736 17.28 2.76 ;
    END
  END i[5]
  PIN i[60]
    DIRECTION INPUT ;
    USE SIGNAL ;
    PORT
      LAYER M4 ;
        RECT  17.088 8.304 17.28 8.328 ;
    END
  END i[60]
  PIN i[61]
    DIRECTION INPUT ;
    USE SIGNAL ;
    PORT
      LAYER M4 ;
        RECT  17.088 8.448 17.28 8.472 ;
    END
  END i[61]
  PIN i[62]
    DIRECTION INPUT ;
    USE SIGNAL ;
    PORT
      LAYER M4 ;
        RECT  17.088 8.544 17.28 8.568 ;
    END
  END i[62]
  PIN i[63]
    DIRECTION INPUT ;
    USE SIGNAL ;
    PORT
      LAYER M4 ;
        RECT  17.088 8.64 17.28 8.664 ;
    END
  END i[63]
  PIN i[64]
    DIRECTION INPUT ;
    USE SIGNAL ;
    PORT
      LAYER M4 ;
        RECT  17.088 8.736 17.28 8.76 ;
    END
  END i[64]
  PIN i[65]
    DIRECTION INPUT ;
    USE SIGNAL ;
    PORT
      LAYER M4 ;
        RECT  17.088 8.832 17.28 8.856 ;
    END
  END i[65]
  PIN i[66]
    DIRECTION INPUT ;
    USE SIGNAL ;
    PORT
      LAYER M4 ;
        RECT  17.088 8.928 17.28 8.952 ;
    END
  END i[66]
  PIN i[67]
    DIRECTION INPUT ;
    USE SIGNAL ;
    PORT
      LAYER M4 ;
        RECT  17.088 9.024 17.28 9.048 ;
    END
  END i[67]
  PIN i[68]
    DIRECTION INPUT ;
    USE SIGNAL ;
    PORT
      LAYER M4 ;
        RECT  17.088 9.12 17.28 9.144 ;
    END
  END i[68]
  PIN i[69]
    DIRECTION INPUT ;
    USE SIGNAL ;
    PORT
      LAYER M4 ;
        RECT  17.088 9.264 17.28 9.288 ;
    END
  END i[69]
  PIN i[6]
    DIRECTION INPUT ;
    USE SIGNAL ;
    PORT
      LAYER M4 ;
        RECT  17.088 2.832 17.28 2.856 ;
    END
  END i[6]
  PIN i[70]
    DIRECTION INPUT ;
    USE SIGNAL ;
    PORT
      LAYER M4 ;
        RECT  17.088 9.36 17.28 9.384 ;
    END
  END i[70]
  PIN i[71]
    DIRECTION INPUT ;
    USE SIGNAL ;
    PORT
      LAYER M4 ;
        RECT  17.088 9.456 17.28 9.48 ;
    END
  END i[71]
  PIN i[72]
    DIRECTION INPUT ;
    USE SIGNAL ;
    PORT
      LAYER M4 ;
        RECT  17.088 9.552 17.28 9.576 ;
    END
  END i[72]
  PIN i[73]
    DIRECTION INPUT ;
    USE SIGNAL ;
    PORT
      LAYER M4 ;
        RECT  17.088 9.648 17.28 9.672 ;
    END
  END i[73]
  PIN i[74]
    DIRECTION INPUT ;
    USE SIGNAL ;
    PORT
      LAYER M4 ;
        RECT  17.088 9.744 17.28 9.768 ;
    END
  END i[74]
  PIN i[75]
    DIRECTION INPUT ;
    USE SIGNAL ;
    PORT
      LAYER M4 ;
        RECT  17.088 9.84 17.28 9.864 ;
    END
  END i[75]
  PIN i[76]
    DIRECTION INPUT ;
    USE SIGNAL ;
    PORT
      LAYER M4 ;
        RECT  17.088 9.936 17.28 9.96 ;
    END
  END i[76]
  PIN i[77]
    DIRECTION INPUT ;
    USE SIGNAL ;
    PORT
      LAYER M4 ;
        RECT  17.088 10.08 17.28 10.104 ;
    END
  END i[77]
  PIN i[78]
    DIRECTION INPUT ;
    USE SIGNAL ;
    PORT
      LAYER M4 ;
        RECT  17.088 10.176 17.28 10.2 ;
    END
  END i[78]
  PIN i[79]
    DIRECTION INPUT ;
    USE SIGNAL ;
    PORT
      LAYER M4 ;
        RECT  17.088 10.272 17.28 10.296 ;
    END
  END i[79]
  PIN i[7]
    DIRECTION INPUT ;
    USE SIGNAL ;
    PORT
      LAYER M4 ;
        RECT  17.088 2.928 17.28 2.952 ;
    END
  END i[7]
  PIN i[80]
    DIRECTION INPUT ;
    USE SIGNAL ;
    PORT
      LAYER M4 ;
        RECT  17.088 10.368 17.28 10.392 ;
    END
  END i[80]
  PIN i[81]
    DIRECTION INPUT ;
    USE SIGNAL ;
    PORT
      LAYER M4 ;
        RECT  17.088 10.464 17.28 10.488 ;
    END
  END i[81]
  PIN i[82]
    DIRECTION INPUT ;
    USE SIGNAL ;
    PORT
      LAYER M4 ;
        RECT  17.088 10.56 17.28 10.584 ;
    END
  END i[82]
  PIN i[83]
    DIRECTION INPUT ;
    USE SIGNAL ;
    PORT
      LAYER M4 ;
        RECT  17.088 10.656 17.28 10.68 ;
    END
  END i[83]
  PIN i[84]
    DIRECTION INPUT ;
    USE SIGNAL ;
    PORT
      LAYER M4 ;
        RECT  17.088 10.752 17.28 10.776 ;
    END
  END i[84]
  PIN i[85]
    DIRECTION INPUT ;
    USE SIGNAL ;
    PORT
      LAYER M4 ;
        RECT  17.088 10.848 17.28 10.872 ;
    END
  END i[85]
  PIN i[86]
    DIRECTION INPUT ;
    USE SIGNAL ;
    PORT
      LAYER M4 ;
        RECT  17.088 10.992 17.28 11.016 ;
    END
  END i[86]
  PIN i[87]
    DIRECTION INPUT ;
    USE SIGNAL ;
    PORT
      LAYER M4 ;
        RECT  17.088 11.088 17.28 11.112 ;
    END
  END i[87]
  PIN i[88]
    DIRECTION INPUT ;
    USE SIGNAL ;
    PORT
      LAYER M4 ;
        RECT  17.088 11.184 17.28 11.208 ;
    END
  END i[88]
  PIN i[89]
    DIRECTION INPUT ;
    USE SIGNAL ;
    PORT
      LAYER M4 ;
        RECT  17.088 11.28 17.28 11.304 ;
    END
  END i[89]
  PIN i[8]
    DIRECTION INPUT ;
    USE SIGNAL ;
    PORT
      LAYER M4 ;
        RECT  17.088 3.024 17.28 3.048 ;
    END
  END i[8]
  PIN i[90]
    DIRECTION INPUT ;
    USE SIGNAL ;
    PORT
      LAYER M4 ;
        RECT  17.088 11.376 17.28 11.4 ;
    END
  END i[90]
  PIN i[91]
    DIRECTION INPUT ;
    USE SIGNAL ;
    PORT
      LAYER M4 ;
        RECT  17.088 11.472 17.28 11.496 ;
    END
  END i[91]
  PIN i[92]
    DIRECTION INPUT ;
    USE SIGNAL ;
    PORT
      LAYER M4 ;
        RECT  17.088 11.568 17.28 11.592 ;
    END
  END i[92]
  PIN i[93]
    DIRECTION INPUT ;
    USE SIGNAL ;
    PORT
      LAYER M4 ;
        RECT  17.088 11.664 17.28 11.688 ;
    END
  END i[93]
  PIN i[94]
    DIRECTION INPUT ;
    USE SIGNAL ;
    PORT
      LAYER M4 ;
        RECT  17.088 11.808 17.28 11.832 ;
    END
  END i[94]
  PIN i[95]
    DIRECTION INPUT ;
    USE SIGNAL ;
    PORT
      LAYER M4 ;
        RECT  17.088 11.904 17.28 11.928 ;
    END
  END i[95]
  PIN i[96]
    DIRECTION INPUT ;
    USE SIGNAL ;
    PORT
      LAYER M4 ;
        RECT  17.088 12 17.28 12.024 ;
    END
  END i[96]
  PIN i[97]
    DIRECTION INPUT ;
    USE SIGNAL ;
    PORT
      LAYER M4 ;
        RECT  17.088 12.096 17.28 12.12 ;
    END
  END i[97]
  PIN i[98]
    DIRECTION INPUT ;
    USE SIGNAL ;
    PORT
      LAYER M4 ;
        RECT  17.088 12.192 17.28 12.216 ;
    END
  END i[98]
  PIN i[99]
    DIRECTION INPUT ;
    USE SIGNAL ;
    PORT
      LAYER M4 ;
        RECT  17.088 12.288 17.28 12.312 ;
    END
  END i[99]
  PIN i[9]
    DIRECTION INPUT ;
    USE SIGNAL ;
    PORT
      LAYER M4 ;
        RECT  17.088 3.12 17.28 3.144 ;
    END
  END i[9]
  PIN o[0]
    DIRECTION OUTPUT ;
    USE SIGNAL ;
    PORT
      LAYER M4 ;
        RECT  0 2.208 0.192 2.232 ;
    END
  END o[0]
  PIN o[100]
    DIRECTION OUTPUT ;
    USE SIGNAL ;
    PORT
      LAYER M4 ;
        RECT  0 12.336 0.192 12.36 ;
    END
  END o[100]
  PIN o[101]
    DIRECTION OUTPUT ;
    USE SIGNAL ;
    PORT
      LAYER M4 ;
        RECT  0 12.48 0.192 12.504 ;
    END
  END o[101]
  PIN o[102]
    DIRECTION OUTPUT ;
    USE SIGNAL ;
    PORT
      LAYER M4 ;
        RECT  0 12.576 0.192 12.6 ;
    END
  END o[102]
  PIN o[103]
    DIRECTION OUTPUT ;
    USE SIGNAL ;
    PORT
      LAYER M4 ;
        RECT  0 12.672 0.192 12.696 ;
    END
  END o[103]
  PIN o[104]
    DIRECTION OUTPUT ;
    USE SIGNAL ;
    PORT
      LAYER M4 ;
        RECT  0 12.768 0.192 12.792 ;
    END
  END o[104]
  PIN o[105]
    DIRECTION OUTPUT ;
    USE SIGNAL ;
    PORT
      LAYER M4 ;
        RECT  0 12.864 0.192 12.888 ;
    END
  END o[105]
  PIN o[106]
    DIRECTION OUTPUT ;
    USE SIGNAL ;
    PORT
      LAYER M4 ;
        RECT  0 12.96 0.192 12.984 ;
    END
  END o[106]
  PIN o[107]
    DIRECTION OUTPUT ;
    USE SIGNAL ;
    PORT
      LAYER M4 ;
        RECT  0 13.056 0.192 13.08 ;
    END
  END o[107]
  PIN o[108]
    DIRECTION OUTPUT ;
    USE SIGNAL ;
    PORT
      LAYER M4 ;
        RECT  0 13.152 0.192 13.176 ;
    END
  END o[108]
  PIN o[109]
    DIRECTION OUTPUT ;
    USE SIGNAL ;
    PORT
      LAYER M4 ;
        RECT  0 13.296 0.192 13.32 ;
    END
  END o[109]
  PIN o[10]
    DIRECTION OUTPUT ;
    USE SIGNAL ;
    PORT
      LAYER M4 ;
        RECT  0 3.216 0.192 3.24 ;
    END
  END o[10]
  PIN o[110]
    DIRECTION OUTPUT ;
    USE SIGNAL ;
    PORT
      LAYER M4 ;
        RECT  0 13.392 0.192 13.416 ;
    END
  END o[110]
  PIN o[111]
    DIRECTION OUTPUT ;
    USE SIGNAL ;
    PORT
      LAYER M4 ;
        RECT  0 13.488 0.192 13.512 ;
    END
  END o[111]
  PIN o[112]
    DIRECTION OUTPUT ;
    USE SIGNAL ;
    PORT
      LAYER M4 ;
        RECT  0 13.584 0.192 13.608 ;
    END
  END o[112]
  PIN o[113]
    DIRECTION OUTPUT ;
    USE SIGNAL ;
    PORT
      LAYER M4 ;
        RECT  0 13.68 0.192 13.704 ;
    END
  END o[113]
  PIN o[114]
    DIRECTION OUTPUT ;
    USE SIGNAL ;
    PORT
      LAYER M4 ;
        RECT  0 13.776 0.192 13.8 ;
    END
  END o[114]
  PIN o[115]
    DIRECTION OUTPUT ;
    USE SIGNAL ;
    PORT
      LAYER M4 ;
        RECT  0 13.872 0.192 13.896 ;
    END
  END o[115]
  PIN o[116]
    DIRECTION OUTPUT ;
    USE SIGNAL ;
    PORT
      LAYER M4 ;
        RECT  0 13.968 0.192 13.992 ;
    END
  END o[116]
  PIN o[117]
    DIRECTION OUTPUT ;
    USE SIGNAL ;
    PORT
      LAYER M4 ;
        RECT  0 14.064 0.192 14.088 ;
    END
  END o[117]
  PIN o[118]
    DIRECTION OUTPUT ;
    USE SIGNAL ;
    PORT
      LAYER M4 ;
        RECT  0 14.208 0.192 14.232 ;
    END
  END o[118]
  PIN o[119]
    DIRECTION OUTPUT ;
    USE SIGNAL ;
    PORT
      LAYER M4 ;
        RECT  0 14.304 0.192 14.328 ;
    END
  END o[119]
  PIN o[11]
    DIRECTION OUTPUT ;
    USE SIGNAL ;
    PORT
      LAYER M4 ;
        RECT  0 3.36 0.192 3.384 ;
    END
  END o[11]
  PIN o[120]
    DIRECTION OUTPUT ;
    USE SIGNAL ;
    PORT
      LAYER M4 ;
        RECT  0 14.4 0.192 14.424 ;
    END
  END o[120]
  PIN o[121]
    DIRECTION OUTPUT ;
    USE SIGNAL ;
    PORT
      LAYER M4 ;
        RECT  0 14.496 0.192 14.52 ;
    END
  END o[121]
  PIN o[122]
    DIRECTION OUTPUT ;
    USE SIGNAL ;
    PORT
      LAYER M4 ;
        RECT  0 14.592 0.192 14.616 ;
    END
  END o[122]
  PIN o[123]
    DIRECTION OUTPUT ;
    USE SIGNAL ;
    PORT
      LAYER M4 ;
        RECT  0 14.688 0.192 14.712 ;
    END
  END o[123]
  PIN o[124]
    DIRECTION OUTPUT ;
    USE SIGNAL ;
    PORT
      LAYER M4 ;
        RECT  0 14.784 0.192 14.808 ;
    END
  END o[124]
  PIN o[125]
    DIRECTION OUTPUT ;
    USE SIGNAL ;
    PORT
      LAYER M4 ;
        RECT  0 14.88 0.192 14.904 ;
    END
  END o[125]
  PIN o[126]
    DIRECTION OUTPUT ;
    USE SIGNAL ;
    PORT
      LAYER M4 ;
        RECT  0 14.976 0.192 15 ;
    END
  END o[126]
  PIN o[127]
    DIRECTION OUTPUT ;
    USE SIGNAL ;
    PORT
      LAYER M4 ;
        RECT  0 15.12 0.192 15.144 ;
    END
  END o[127]
  PIN o[128]
    DIRECTION OUTPUT ;
    USE SIGNAL ;
    PORT
      LAYER M4 ;
        RECT  0 15.216 0.192 15.24 ;
    END
  END o[128]
  PIN o[129]
    DIRECTION OUTPUT ;
    USE SIGNAL ;
    PORT
      LAYER M4 ;
        RECT  0 15.312 0.192 15.336 ;
    END
  END o[129]
  PIN o[12]
    DIRECTION OUTPUT ;
    USE SIGNAL ;
    PORT
      LAYER M4 ;
        RECT  0 3.456 0.192 3.48 ;
    END
  END o[12]
  PIN o[130]
    DIRECTION OUTPUT ;
    USE SIGNAL ;
    PORT
      LAYER M4 ;
        RECT  0 15.408 0.192 15.432 ;
    END
  END o[130]
  PIN o[131]
    DIRECTION OUTPUT ;
    USE SIGNAL ;
    PORT
      LAYER M4 ;
        RECT  0 15.504 0.192 15.528 ;
    END
  END o[131]
  PIN o[132]
    DIRECTION OUTPUT ;
    USE SIGNAL ;
    PORT
      LAYER M4 ;
        RECT  0 15.6 0.192 15.624 ;
    END
  END o[132]
  PIN o[133]
    DIRECTION OUTPUT ;
    USE SIGNAL ;
    PORT
      LAYER M4 ;
        RECT  0 15.696 0.192 15.72 ;
    END
  END o[133]
  PIN o[134]
    DIRECTION OUTPUT ;
    USE SIGNAL ;
    PORT
      LAYER M4 ;
        RECT  0 15.792 0.192 15.816 ;
    END
  END o[134]
  PIN o[135]
    DIRECTION OUTPUT ;
    USE SIGNAL ;
    PORT
      LAYER M4 ;
        RECT  0 15.888 0.192 15.912 ;
    END
  END o[135]
  PIN o[136]
    DIRECTION OUTPUT ;
    USE SIGNAL ;
    PORT
      LAYER M4 ;
        RECT  0 16.032 0.192 16.056 ;
    END
  END o[136]
  PIN o[137]
    DIRECTION OUTPUT ;
    USE SIGNAL ;
    PORT
      LAYER M4 ;
        RECT  0 16.128 0.192 16.152 ;
    END
  END o[137]
  PIN o[138]
    DIRECTION OUTPUT ;
    USE SIGNAL ;
    PORT
      LAYER M4 ;
        RECT  0 16.32 0.192 16.344 ;
    END
  END o[138]
  PIN o[139]
    DIRECTION OUTPUT ;
    USE SIGNAL ;
    PORT
      LAYER M4 ;
        RECT  0 16.416 0.192 16.44 ;
    END
  END o[139]
  PIN o[13]
    DIRECTION OUTPUT ;
    USE SIGNAL ;
    PORT
      LAYER M4 ;
        RECT  0 3.552 0.192 3.576 ;
    END
  END o[13]
  PIN o[140]
    DIRECTION OUTPUT ;
    USE SIGNAL ;
    PORT
      LAYER M4 ;
        RECT  0 16.512 0.192 16.536 ;
    END
  END o[140]
  PIN o[141]
    DIRECTION OUTPUT ;
    USE SIGNAL ;
    PORT
      LAYER M4 ;
        RECT  0 16.608 0.192 16.632 ;
    END
  END o[141]
  PIN o[142]
    DIRECTION OUTPUT ;
    USE SIGNAL ;
    PORT
      LAYER M4 ;
        RECT  0 16.704 0.192 16.728 ;
    END
  END o[142]
  PIN o[143]
    DIRECTION OUTPUT ;
    USE SIGNAL ;
    PORT
      LAYER M4 ;
        RECT  0 16.8 0.192 16.824 ;
    END
  END o[143]
  PIN o[144]
    DIRECTION OUTPUT ;
    USE SIGNAL ;
    PORT
      LAYER M4 ;
        RECT  0 16.944 0.192 16.968 ;
    END
  END o[144]
  PIN o[145]
    DIRECTION OUTPUT ;
    USE SIGNAL ;
    PORT
      LAYER M4 ;
        RECT  0 17.04 0.192 17.064 ;
    END
  END o[145]
  PIN o[146]
    DIRECTION OUTPUT ;
    USE SIGNAL ;
    PORT
      LAYER M4 ;
        RECT  0 17.136 0.192 17.16 ;
    END
  END o[146]
  PIN o[147]
    DIRECTION OUTPUT ;
    USE SIGNAL ;
    PORT
      LAYER M4 ;
        RECT  0 17.232 0.192 17.256 ;
    END
  END o[147]
  PIN o[148]
    DIRECTION OUTPUT ;
    USE SIGNAL ;
    PORT
      LAYER M4 ;
        RECT  0 17.328 0.192 17.352 ;
    END
  END o[148]
  PIN o[149]
    DIRECTION OUTPUT ;
    USE SIGNAL ;
    PORT
      LAYER M4 ;
        RECT  0 17.424 0.192 17.448 ;
    END
  END o[149]
  PIN o[14]
    DIRECTION OUTPUT ;
    USE SIGNAL ;
    PORT
      LAYER M4 ;
        RECT  0 3.648 0.192 3.672 ;
    END
  END o[14]
  PIN o[150]
    DIRECTION OUTPUT ;
    USE SIGNAL ;
    PORT
      LAYER M4 ;
        RECT  0 17.52 0.192 17.544 ;
    END
  END o[150]
  PIN o[151]
    DIRECTION OUTPUT ;
    USE SIGNAL ;
    PORT
      LAYER M4 ;
        RECT  0 17.616 0.192 17.64 ;
    END
  END o[151]
  PIN o[152]
    DIRECTION OUTPUT ;
    USE SIGNAL ;
    PORT
      LAYER M4 ;
        RECT  0 17.712 0.192 17.736 ;
    END
  END o[152]
  PIN o[153]
    DIRECTION OUTPUT ;
    USE SIGNAL ;
    PORT
      LAYER M4 ;
        RECT  0 17.856 0.192 17.88 ;
    END
  END o[153]
  PIN o[154]
    DIRECTION OUTPUT ;
    USE SIGNAL ;
    PORT
      LAYER M4 ;
        RECT  0 17.952 0.192 17.976 ;
    END
  END o[154]
  PIN o[155]
    DIRECTION OUTPUT ;
    USE SIGNAL ;
    PORT
      LAYER M4 ;
        RECT  0 18.048 0.192 18.072 ;
    END
  END o[155]
  PIN o[156]
    DIRECTION OUTPUT ;
    USE SIGNAL ;
    PORT
      LAYER M4 ;
        RECT  0 18.144 0.192 18.168 ;
    END
  END o[156]
  PIN o[157]
    DIRECTION OUTPUT ;
    USE SIGNAL ;
    PORT
      LAYER M4 ;
        RECT  0 18.24 0.192 18.264 ;
    END
  END o[157]
  PIN o[158]
    DIRECTION OUTPUT ;
    USE SIGNAL ;
    PORT
      LAYER M4 ;
        RECT  0 18.336 0.192 18.36 ;
    END
  END o[158]
  PIN o[159]
    DIRECTION OUTPUT ;
    USE SIGNAL ;
    PORT
      LAYER M4 ;
        RECT  0 18.432 0.192 18.456 ;
    END
  END o[159]
  PIN o[15]
    DIRECTION OUTPUT ;
    USE SIGNAL ;
    PORT
      LAYER M4 ;
        RECT  0 3.744 0.192 3.768 ;
    END
  END o[15]
  PIN o[160]
    DIRECTION OUTPUT ;
    USE SIGNAL ;
    PORT
      LAYER M4 ;
        RECT  0 18.528 0.192 18.552 ;
    END
  END o[160]
  PIN o[161]
    DIRECTION OUTPUT ;
    USE SIGNAL ;
    PORT
      LAYER M4 ;
        RECT  0 18.624 0.192 18.648 ;
    END
  END o[161]
  PIN o[162]
    DIRECTION OUTPUT ;
    USE SIGNAL ;
    PORT
      LAYER M4 ;
        RECT  0 18.768 0.192 18.792 ;
    END
  END o[162]
  PIN o[163]
    DIRECTION OUTPUT ;
    USE SIGNAL ;
    PORT
      LAYER M4 ;
        RECT  0 18.864 0.192 18.888 ;
    END
  END o[163]
  PIN o[164]
    DIRECTION OUTPUT ;
    USE SIGNAL ;
    PORT
      LAYER M4 ;
        RECT  0 18.96 0.192 18.984 ;
    END
  END o[164]
  PIN o[165]
    DIRECTION OUTPUT ;
    USE SIGNAL ;
    PORT
      LAYER M4 ;
        RECT  0 19.056 0.192 19.08 ;
    END
  END o[165]
  PIN o[166]
    DIRECTION OUTPUT ;
    USE SIGNAL ;
    PORT
      LAYER M4 ;
        RECT  0 19.152 0.192 19.176 ;
    END
  END o[166]
  PIN o[167]
    DIRECTION OUTPUT ;
    USE SIGNAL ;
    PORT
      LAYER M4 ;
        RECT  0 19.248 0.192 19.272 ;
    END
  END o[167]
  PIN o[168]
    DIRECTION OUTPUT ;
    USE SIGNAL ;
    PORT
      LAYER M4 ;
        RECT  0 19.344 0.192 19.368 ;
    END
  END o[168]
  PIN o[169]
    DIRECTION OUTPUT ;
    USE SIGNAL ;
    PORT
      LAYER M4 ;
        RECT  0 19.44 0.192 19.464 ;
    END
  END o[169]
  PIN o[16]
    DIRECTION OUTPUT ;
    USE SIGNAL ;
    PORT
      LAYER M4 ;
        RECT  0 3.84 0.192 3.864 ;
    END
  END o[16]
  PIN o[170]
    DIRECTION OUTPUT ;
    USE SIGNAL ;
    PORT
      LAYER M4 ;
        RECT  0 19.536 0.192 19.56 ;
    END
  END o[170]
  PIN o[171]
    DIRECTION OUTPUT ;
    USE SIGNAL ;
    PORT
      LAYER M4 ;
        RECT  0 19.68 0.192 19.704 ;
    END
  END o[171]
  PIN o[172]
    DIRECTION OUTPUT ;
    USE SIGNAL ;
    PORT
      LAYER M4 ;
        RECT  0 19.776 0.192 19.8 ;
    END
  END o[172]
  PIN o[173]
    DIRECTION OUTPUT ;
    USE SIGNAL ;
    PORT
      LAYER M4 ;
        RECT  0 19.872 0.192 19.896 ;
    END
  END o[173]
  PIN o[174]
    DIRECTION OUTPUT ;
    USE SIGNAL ;
    PORT
      LAYER M4 ;
        RECT  0 19.968 0.192 19.992 ;
    END
  END o[174]
  PIN o[175]
    DIRECTION OUTPUT ;
    USE SIGNAL ;
    PORT
      LAYER M4 ;
        RECT  0 20.064 0.192 20.088 ;
    END
  END o[175]
  PIN o[176]
    DIRECTION OUTPUT ;
    USE SIGNAL ;
    PORT
      LAYER M4 ;
        RECT  0 20.16 0.192 20.184 ;
    END
  END o[176]
  PIN o[177]
    DIRECTION OUTPUT ;
    USE SIGNAL ;
    PORT
      LAYER M4 ;
        RECT  0 20.256 0.192 20.28 ;
    END
  END o[177]
  PIN o[178]
    DIRECTION OUTPUT ;
    USE SIGNAL ;
    PORT
      LAYER M4 ;
        RECT  0 20.352 0.192 20.376 ;
    END
  END o[178]
  PIN o[179]
    DIRECTION OUTPUT ;
    USE SIGNAL ;
    PORT
      LAYER M4 ;
        RECT  0 20.448 0.192 20.472 ;
    END
  END o[179]
  PIN o[17]
    DIRECTION OUTPUT ;
    USE SIGNAL ;
    PORT
      LAYER M4 ;
        RECT  0 3.936 0.192 3.96 ;
    END
  END o[17]
  PIN o[180]
    DIRECTION OUTPUT ;
    USE SIGNAL ;
    PORT
      LAYER M4 ;
        RECT  0 20.592 0.192 20.616 ;
    END
  END o[180]
  PIN o[181]
    DIRECTION OUTPUT ;
    USE SIGNAL ;
    PORT
      LAYER M4 ;
        RECT  0 20.688 0.192 20.712 ;
    END
  END o[181]
  PIN o[182]
    DIRECTION OUTPUT ;
    USE SIGNAL ;
    PORT
      LAYER M4 ;
        RECT  0 20.784 0.192 20.808 ;
    END
  END o[182]
  PIN o[183]
    DIRECTION OUTPUT ;
    USE SIGNAL ;
    PORT
      LAYER M4 ;
        RECT  0 20.88 0.192 20.904 ;
    END
  END o[183]
  PIN o[184]
    DIRECTION OUTPUT ;
    USE SIGNAL ;
    PORT
      LAYER M4 ;
        RECT  0 20.976 0.192 21 ;
    END
  END o[184]
  PIN o[185]
    DIRECTION OUTPUT ;
    USE SIGNAL ;
    PORT
      LAYER M4 ;
        RECT  0 21.072 0.192 21.096 ;
    END
  END o[185]
  PIN o[186]
    DIRECTION OUTPUT ;
    USE SIGNAL ;
    PORT
      LAYER M4 ;
        RECT  0 21.168 0.192 21.192 ;
    END
  END o[186]
  PIN o[187]
    DIRECTION OUTPUT ;
    USE SIGNAL ;
    PORT
      LAYER M4 ;
        RECT  0 21.264 0.192 21.288 ;
    END
  END o[187]
  PIN o[188]
    DIRECTION OUTPUT ;
    USE SIGNAL ;
    PORT
      LAYER M4 ;
        RECT  0 21.36 0.192 21.384 ;
    END
  END o[188]
  PIN o[189]
    DIRECTION OUTPUT ;
    USE SIGNAL ;
    PORT
      LAYER M4 ;
        RECT  0 21.504 0.192 21.528 ;
    END
  END o[189]
  PIN o[18]
    DIRECTION OUTPUT ;
    USE SIGNAL ;
    PORT
      LAYER M4 ;
        RECT  0 4.032 0.192 4.056 ;
    END
  END o[18]
  PIN o[190]
    DIRECTION OUTPUT ;
    USE SIGNAL ;
    PORT
      LAYER M4 ;
        RECT  0 21.6 0.192 21.624 ;
    END
  END o[190]
  PIN o[191]
    DIRECTION OUTPUT ;
    USE SIGNAL ;
    PORT
      LAYER M4 ;
        RECT  0 21.696 0.192 21.72 ;
    END
  END o[191]
  PIN o[192]
    DIRECTION OUTPUT ;
    USE SIGNAL ;
    PORT
      LAYER M4 ;
        RECT  0 21.792 0.192 21.816 ;
    END
  END o[192]
  PIN o[193]
    DIRECTION OUTPUT ;
    USE SIGNAL ;
    PORT
      LAYER M4 ;
        RECT  0 21.888 0.192 21.912 ;
    END
  END o[193]
  PIN o[194]
    DIRECTION OUTPUT ;
    USE SIGNAL ;
    PORT
      LAYER M4 ;
        RECT  0 21.984 0.192 22.008 ;
    END
  END o[194]
  PIN o[195]
    DIRECTION OUTPUT ;
    USE SIGNAL ;
    PORT
      LAYER M4 ;
        RECT  0 22.08 0.192 22.104 ;
    END
  END o[195]
  PIN o[196]
    DIRECTION OUTPUT ;
    USE SIGNAL ;
    PORT
      LAYER M4 ;
        RECT  0 22.176 0.192 22.2 ;
    END
  END o[196]
  PIN o[197]
    DIRECTION OUTPUT ;
    USE SIGNAL ;
    PORT
      LAYER M4 ;
        RECT  0 22.272 0.192 22.296 ;
    END
  END o[197]
  PIN o[198]
    DIRECTION OUTPUT ;
    USE SIGNAL ;
    PORT
      LAYER M4 ;
        RECT  0 22.416 0.192 22.44 ;
    END
  END o[198]
  PIN o[199]
    DIRECTION OUTPUT ;
    USE SIGNAL ;
    PORT
      LAYER M4 ;
        RECT  0 22.512 0.192 22.536 ;
    END
  END o[199]
  PIN o[19]
    DIRECTION OUTPUT ;
    USE SIGNAL ;
    PORT
      LAYER M4 ;
        RECT  0 4.128 0.192 4.152 ;
    END
  END o[19]
  PIN o[1]
    DIRECTION OUTPUT ;
    USE SIGNAL ;
    PORT
      LAYER M4 ;
        RECT  0 2.304 0.192 2.328 ;
    END
  END o[1]
  PIN o[200]
    DIRECTION OUTPUT ;
    USE SIGNAL ;
    PORT
      LAYER M4 ;
        RECT  0 22.608 0.192 22.632 ;
    END
  END o[200]
  PIN o[201]
    DIRECTION OUTPUT ;
    USE SIGNAL ;
    PORT
      LAYER M4 ;
        RECT  0 22.704 0.192 22.728 ;
    END
  END o[201]
  PIN o[202]
    DIRECTION OUTPUT ;
    USE SIGNAL ;
    PORT
      LAYER M4 ;
        RECT  0 22.8 0.192 22.824 ;
    END
  END o[202]
  PIN o[203]
    DIRECTION OUTPUT ;
    USE SIGNAL ;
    PORT
      LAYER M4 ;
        RECT  0 22.896 0.192 22.92 ;
    END
  END o[203]
  PIN o[204]
    DIRECTION OUTPUT ;
    USE SIGNAL ;
    PORT
      LAYER M4 ;
        RECT  0 22.992 0.192 23.016 ;
    END
  END o[204]
  PIN o[205]
    DIRECTION OUTPUT ;
    USE SIGNAL ;
    PORT
      LAYER M4 ;
        RECT  0 23.088 0.192 23.112 ;
    END
  END o[205]
  PIN o[206]
    DIRECTION OUTPUT ;
    USE SIGNAL ;
    PORT
      LAYER M4 ;
        RECT  0 23.184 0.192 23.208 ;
    END
  END o[206]
  PIN o[207]
    DIRECTION OUTPUT ;
    USE SIGNAL ;
    PORT
      LAYER M4 ;
        RECT  0 23.328 0.192 23.352 ;
    END
  END o[207]
  PIN o[208]
    DIRECTION OUTPUT ;
    USE SIGNAL ;
    PORT
      LAYER M4 ;
        RECT  0 23.424 0.192 23.448 ;
    END
  END o[208]
  PIN o[209]
    DIRECTION OUTPUT ;
    USE SIGNAL ;
    PORT
      LAYER M4 ;
        RECT  0 23.52 0.192 23.544 ;
    END
  END o[209]
  PIN o[20]
    DIRECTION OUTPUT ;
    USE SIGNAL ;
    PORT
      LAYER M4 ;
        RECT  0 4.272 0.192 4.296 ;
    END
  END o[20]
  PIN o[210]
    DIRECTION OUTPUT ;
    USE SIGNAL ;
    PORT
      LAYER M4 ;
        RECT  0 23.616 0.192 23.64 ;
    END
  END o[210]
  PIN o[211]
    DIRECTION OUTPUT ;
    USE SIGNAL ;
    PORT
      LAYER M4 ;
        RECT  0 23.712 0.192 23.736 ;
    END
  END o[211]
  PIN o[212]
    DIRECTION OUTPUT ;
    USE SIGNAL ;
    PORT
      LAYER M4 ;
        RECT  0 23.808 0.192 23.832 ;
    END
  END o[212]
  PIN o[213]
    DIRECTION OUTPUT ;
    USE SIGNAL ;
    PORT
      LAYER M4 ;
        RECT  0 23.904 0.192 23.928 ;
    END
  END o[213]
  PIN o[214]
    DIRECTION OUTPUT ;
    USE SIGNAL ;
    PORT
      LAYER M4 ;
        RECT  0 24 0.192 24.024 ;
    END
  END o[214]
  PIN o[215]
    DIRECTION OUTPUT ;
    USE SIGNAL ;
    PORT
      LAYER M4 ;
        RECT  0 24.096 0.192 24.12 ;
    END
  END o[215]
  PIN o[216]
    DIRECTION OUTPUT ;
    USE SIGNAL ;
    PORT
      LAYER M4 ;
        RECT  0 24.24 0.192 24.264 ;
    END
  END o[216]
  PIN o[217]
    DIRECTION OUTPUT ;
    USE SIGNAL ;
    PORT
      LAYER M4 ;
        RECT  0 24.336 0.192 24.36 ;
    END
  END o[217]
  PIN o[218]
    DIRECTION OUTPUT ;
    USE SIGNAL ;
    PORT
      LAYER M4 ;
        RECT  0 24.432 0.192 24.456 ;
    END
  END o[218]
  PIN o[219]
    DIRECTION OUTPUT ;
    USE SIGNAL ;
    PORT
      LAYER M4 ;
        RECT  0 24.528 0.192 24.552 ;
    END
  END o[219]
  PIN o[21]
    DIRECTION OUTPUT ;
    USE SIGNAL ;
    PORT
      LAYER M4 ;
        RECT  0 4.368 0.192 4.392 ;
    END
  END o[21]
  PIN o[220]
    DIRECTION OUTPUT ;
    USE SIGNAL ;
    PORT
      LAYER M4 ;
        RECT  0 24.624 0.192 24.648 ;
    END
  END o[220]
  PIN o[221]
    DIRECTION OUTPUT ;
    USE SIGNAL ;
    PORT
      LAYER M4 ;
        RECT  0 24.72 0.192 24.744 ;
    END
  END o[221]
  PIN o[222]
    DIRECTION OUTPUT ;
    USE SIGNAL ;
    PORT
      LAYER M4 ;
        RECT  0 24.816 0.192 24.84 ;
    END
  END o[222]
  PIN o[223]
    DIRECTION OUTPUT ;
    USE SIGNAL ;
    PORT
      LAYER M4 ;
        RECT  0 24.912 0.192 24.936 ;
    END
  END o[223]
  PIN o[224]
    DIRECTION OUTPUT ;
    USE SIGNAL ;
    PORT
      LAYER M4 ;
        RECT  0 25.008 0.192 25.032 ;
    END
  END o[224]
  PIN o[225]
    DIRECTION OUTPUT ;
    USE SIGNAL ;
    PORT
      LAYER M4 ;
        RECT  0 25.152 0.192 25.176 ;
    END
  END o[225]
  PIN o[226]
    DIRECTION OUTPUT ;
    USE SIGNAL ;
    PORT
      LAYER M4 ;
        RECT  0 25.248 0.192 25.272 ;
    END
  END o[226]
  PIN o[227]
    DIRECTION OUTPUT ;
    USE SIGNAL ;
    PORT
      LAYER M4 ;
        RECT  0 25.344 0.192 25.368 ;
    END
  END o[227]
  PIN o[228]
    DIRECTION OUTPUT ;
    USE SIGNAL ;
    PORT
      LAYER M4 ;
        RECT  0 25.44 0.192 25.464 ;
    END
  END o[228]
  PIN o[229]
    DIRECTION OUTPUT ;
    USE SIGNAL ;
    PORT
      LAYER M4 ;
        RECT  0 25.536 0.192 25.56 ;
    END
  END o[229]
  PIN o[22]
    DIRECTION OUTPUT ;
    USE SIGNAL ;
    PORT
      LAYER M4 ;
        RECT  0 4.464 0.192 4.488 ;
    END
  END o[22]
  PIN o[230]
    DIRECTION OUTPUT ;
    USE SIGNAL ;
    PORT
      LAYER M4 ;
        RECT  0 25.632 0.192 25.656 ;
    END
  END o[230]
  PIN o[231]
    DIRECTION OUTPUT ;
    USE SIGNAL ;
    PORT
      LAYER M4 ;
        RECT  0 25.728 0.192 25.752 ;
    END
  END o[231]
  PIN o[232]
    DIRECTION OUTPUT ;
    USE SIGNAL ;
    PORT
      LAYER M4 ;
        RECT  0 25.824 0.192 25.848 ;
    END
  END o[232]
  PIN o[233]
    DIRECTION OUTPUT ;
    USE SIGNAL ;
    PORT
      LAYER M4 ;
        RECT  0 25.92 0.192 25.944 ;
    END
  END o[233]
  PIN o[234]
    DIRECTION OUTPUT ;
    USE SIGNAL ;
    PORT
      LAYER M4 ;
        RECT  0 26.064 0.192 26.088 ;
    END
  END o[234]
  PIN o[235]
    DIRECTION OUTPUT ;
    USE SIGNAL ;
    PORT
      LAYER M4 ;
        RECT  0 26.16 0.192 26.184 ;
    END
  END o[235]
  PIN o[236]
    DIRECTION OUTPUT ;
    USE SIGNAL ;
    PORT
      LAYER M4 ;
        RECT  0 26.256 0.192 26.28 ;
    END
  END o[236]
  PIN o[237]
    DIRECTION OUTPUT ;
    USE SIGNAL ;
    PORT
      LAYER M4 ;
        RECT  0 26.352 0.192 26.376 ;
    END
  END o[237]
  PIN o[238]
    DIRECTION OUTPUT ;
    USE SIGNAL ;
    PORT
      LAYER M4 ;
        RECT  0 26.448 0.192 26.472 ;
    END
  END o[238]
  PIN o[239]
    DIRECTION OUTPUT ;
    USE SIGNAL ;
    PORT
      LAYER M4 ;
        RECT  0 26.544 0.192 26.568 ;
    END
  END o[239]
  PIN o[23]
    DIRECTION OUTPUT ;
    USE SIGNAL ;
    PORT
      LAYER M4 ;
        RECT  0 4.56 0.192 4.584 ;
    END
  END o[23]
  PIN o[240]
    DIRECTION OUTPUT ;
    USE SIGNAL ;
    PORT
      LAYER M4 ;
        RECT  0 26.64 0.192 26.664 ;
    END
  END o[240]
  PIN o[241]
    DIRECTION OUTPUT ;
    USE SIGNAL ;
    PORT
      LAYER M4 ;
        RECT  0 26.736 0.192 26.76 ;
    END
  END o[241]
  PIN o[242]
    DIRECTION OUTPUT ;
    USE SIGNAL ;
    PORT
      LAYER M4 ;
        RECT  0 26.88 0.192 26.904 ;
    END
  END o[242]
  PIN o[243]
    DIRECTION OUTPUT ;
    USE SIGNAL ;
    PORT
      LAYER M4 ;
        RECT  0 26.976 0.192 27 ;
    END
  END o[243]
  PIN o[244]
    DIRECTION OUTPUT ;
    USE SIGNAL ;
    PORT
      LAYER M4 ;
        RECT  0 27.072 0.192 27.096 ;
    END
  END o[244]
  PIN o[245]
    DIRECTION OUTPUT ;
    USE SIGNAL ;
    PORT
      LAYER M4 ;
        RECT  0 27.168 0.192 27.192 ;
    END
  END o[245]
  PIN o[246]
    DIRECTION OUTPUT ;
    USE SIGNAL ;
    PORT
      LAYER M4 ;
        RECT  0 27.264 0.192 27.288 ;
    END
  END o[246]
  PIN o[247]
    DIRECTION OUTPUT ;
    USE SIGNAL ;
    PORT
      LAYER M4 ;
        RECT  0 27.36 0.192 27.384 ;
    END
  END o[247]
  PIN o[248]
    DIRECTION OUTPUT ;
    USE SIGNAL ;
    PORT
      LAYER M4 ;
        RECT  0 27.456 0.192 27.48 ;
    END
  END o[248]
  PIN o[249]
    DIRECTION OUTPUT ;
    USE SIGNAL ;
    PORT
      LAYER M4 ;
        RECT  0 27.552 0.192 27.576 ;
    END
  END o[249]
  PIN o[24]
    DIRECTION OUTPUT ;
    USE SIGNAL ;
    PORT
      LAYER M4 ;
        RECT  0 4.656 0.192 4.68 ;
    END
  END o[24]
  PIN o[250]
    DIRECTION OUTPUT ;
    USE SIGNAL ;
    PORT
      LAYER M4 ;
        RECT  0 27.648 0.192 27.672 ;
    END
  END o[250]
  PIN o[251]
    DIRECTION OUTPUT ;
    USE SIGNAL ;
    PORT
      LAYER M4 ;
        RECT  0 27.792 0.192 27.816 ;
    END
  END o[251]
  PIN o[252]
    DIRECTION OUTPUT ;
    USE SIGNAL ;
    PORT
      LAYER M4 ;
        RECT  0 27.888 0.192 27.912 ;
    END
  END o[252]
  PIN o[253]
    DIRECTION OUTPUT ;
    USE SIGNAL ;
    PORT
      LAYER M4 ;
        RECT  0 27.984 0.192 28.008 ;
    END
  END o[253]
  PIN o[254]
    DIRECTION OUTPUT ;
    USE SIGNAL ;
    PORT
      LAYER M4 ;
        RECT  0 28.08 0.192 28.104 ;
    END
  END o[254]
  PIN o[255]
    DIRECTION OUTPUT ;
    USE SIGNAL ;
    PORT
      LAYER M4 ;
        RECT  0 28.176 0.192 28.2 ;
    END
  END o[255]
  PIN o[256]
    DIRECTION OUTPUT ;
    USE SIGNAL ;
    PORT
      LAYER M4 ;
        RECT  0 28.272 0.192 28.296 ;
    END
  END o[256]
  PIN o[257]
    DIRECTION OUTPUT ;
    USE SIGNAL ;
    PORT
      LAYER M4 ;
        RECT  0 28.368 0.192 28.392 ;
    END
  END o[257]
  PIN o[258]
    DIRECTION OUTPUT ;
    USE SIGNAL ;
    PORT
      LAYER M4 ;
        RECT  0 28.464 0.192 28.488 ;
    END
  END o[258]
  PIN o[259]
    DIRECTION OUTPUT ;
    USE SIGNAL ;
    PORT
      LAYER M4 ;
        RECT  0 28.56 0.192 28.584 ;
    END
  END o[259]
  PIN o[25]
    DIRECTION OUTPUT ;
    USE SIGNAL ;
    PORT
      LAYER M4 ;
        RECT  0 4.752 0.192 4.776 ;
    END
  END o[25]
  PIN o[260]
    DIRECTION OUTPUT ;
    USE SIGNAL ;
    PORT
      LAYER M4 ;
        RECT  0 28.704 0.192 28.728 ;
    END
  END o[260]
  PIN o[261]
    DIRECTION OUTPUT ;
    USE SIGNAL ;
    PORT
      LAYER M4 ;
        RECT  0 28.8 0.192 28.824 ;
    END
  END o[261]
  PIN o[262]
    DIRECTION OUTPUT ;
    USE SIGNAL ;
    PORT
      LAYER M4 ;
        RECT  0 28.896 0.192 28.92 ;
    END
  END o[262]
  PIN o[263]
    DIRECTION OUTPUT ;
    USE SIGNAL ;
    PORT
      LAYER M4 ;
        RECT  0 28.992 0.192 29.016 ;
    END
  END o[263]
  PIN o[264]
    DIRECTION OUTPUT ;
    USE SIGNAL ;
    PORT
      LAYER M4 ;
        RECT  0 29.088 0.192 29.112 ;
    END
  END o[264]
  PIN o[265]
    DIRECTION OUTPUT ;
    USE SIGNAL ;
    PORT
      LAYER M4 ;
        RECT  0 29.184 0.192 29.208 ;
    END
  END o[265]
  PIN o[266]
    DIRECTION OUTPUT ;
    USE SIGNAL ;
    PORT
      LAYER M4 ;
        RECT  0 29.28 0.192 29.304 ;
    END
  END o[266]
  PIN o[267]
    DIRECTION OUTPUT ;
    USE SIGNAL ;
    PORT
      LAYER M4 ;
        RECT  0 29.376 0.192 29.4 ;
    END
  END o[267]
  PIN o[268]
    DIRECTION OUTPUT ;
    USE SIGNAL ;
    PORT
      LAYER M4 ;
        RECT  0 29.472 0.192 29.496 ;
    END
  END o[268]
  PIN o[269]
    DIRECTION OUTPUT ;
    USE SIGNAL ;
    PORT
      LAYER M4 ;
        RECT  0 29.616 0.192 29.64 ;
    END
  END o[269]
  PIN o[26]
    DIRECTION OUTPUT ;
    USE SIGNAL ;
    PORT
      LAYER M4 ;
        RECT  0 4.848 0.192 4.872 ;
    END
  END o[26]
  PIN o[270]
    DIRECTION OUTPUT ;
    USE SIGNAL ;
    PORT
      LAYER M4 ;
        RECT  0 29.712 0.192 29.736 ;
    END
  END o[270]
  PIN o[271]
    DIRECTION OUTPUT ;
    USE SIGNAL ;
    PORT
      LAYER M4 ;
        RECT  0 29.808 0.192 29.832 ;
    END
  END o[271]
  PIN o[272]
    DIRECTION OUTPUT ;
    USE SIGNAL ;
    PORT
      LAYER M4 ;
        RECT  0 29.904 0.192 29.928 ;
    END
  END o[272]
  PIN o[273]
    DIRECTION OUTPUT ;
    USE SIGNAL ;
    PORT
      LAYER M4 ;
        RECT  0 30 0.192 30.024 ;
    END
  END o[273]
  PIN o[274]
    DIRECTION OUTPUT ;
    USE SIGNAL ;
    PORT
      LAYER M4 ;
        RECT  0 30.096 0.192 30.12 ;
    END
  END o[274]
  PIN o[275]
    DIRECTION OUTPUT ;
    USE SIGNAL ;
    PORT
      LAYER M4 ;
        RECT  0 30.192 0.192 30.216 ;
    END
  END o[275]
  PIN o[27]
    DIRECTION OUTPUT ;
    USE SIGNAL ;
    PORT
      LAYER M4 ;
        RECT  0 4.944 0.192 4.968 ;
    END
  END o[27]
  PIN o[28]
    DIRECTION OUTPUT ;
    USE SIGNAL ;
    PORT
      LAYER M4 ;
        RECT  0 5.04 0.192 5.064 ;
    END
  END o[28]
  PIN o[29]
    DIRECTION OUTPUT ;
    USE SIGNAL ;
    PORT
      LAYER M4 ;
        RECT  0 5.184 0.192 5.208 ;
    END
  END o[29]
  PIN o[2]
    DIRECTION OUTPUT ;
    USE SIGNAL ;
    PORT
      LAYER M4 ;
        RECT  0 2.448 0.192 2.472 ;
    END
  END o[2]
  PIN o[30]
    DIRECTION OUTPUT ;
    USE SIGNAL ;
    PORT
      LAYER M4 ;
        RECT  0 5.28 0.192 5.304 ;
    END
  END o[30]
  PIN o[31]
    DIRECTION OUTPUT ;
    USE SIGNAL ;
    PORT
      LAYER M4 ;
        RECT  0 5.376 0.192 5.4 ;
    END
  END o[31]
  PIN o[32]
    DIRECTION OUTPUT ;
    USE SIGNAL ;
    PORT
      LAYER M4 ;
        RECT  0 5.472 0.192 5.496 ;
    END
  END o[32]
  PIN o[33]
    DIRECTION OUTPUT ;
    USE SIGNAL ;
    PORT
      LAYER M4 ;
        RECT  0 5.568 0.192 5.592 ;
    END
  END o[33]
  PIN o[34]
    DIRECTION OUTPUT ;
    USE SIGNAL ;
    PORT
      LAYER M4 ;
        RECT  0 5.664 0.192 5.688 ;
    END
  END o[34]
  PIN o[35]
    DIRECTION OUTPUT ;
    USE SIGNAL ;
    PORT
      LAYER M4 ;
        RECT  0 5.76 0.192 5.784 ;
    END
  END o[35]
  PIN o[36]
    DIRECTION OUTPUT ;
    USE SIGNAL ;
    PORT
      LAYER M4 ;
        RECT  0 5.856 0.192 5.88 ;
    END
  END o[36]
  PIN o[37]
    DIRECTION OUTPUT ;
    USE SIGNAL ;
    PORT
      LAYER M4 ;
        RECT  0 5.952 0.192 5.976 ;
    END
  END o[37]
  PIN o[38]
    DIRECTION OUTPUT ;
    USE SIGNAL ;
    PORT
      LAYER M4 ;
        RECT  0 6.096 0.192 6.12 ;
    END
  END o[38]
  PIN o[39]
    DIRECTION OUTPUT ;
    USE SIGNAL ;
    PORT
      LAYER M4 ;
        RECT  0 6.192 0.192 6.216 ;
    END
  END o[39]
  PIN o[3]
    DIRECTION OUTPUT ;
    USE SIGNAL ;
    PORT
      LAYER M4 ;
        RECT  0 2.544 0.192 2.568 ;
    END
  END o[3]
  PIN o[40]
    DIRECTION OUTPUT ;
    USE SIGNAL ;
    PORT
      LAYER M4 ;
        RECT  0 6.288 0.192 6.312 ;
    END
  END o[40]
  PIN o[41]
    DIRECTION OUTPUT ;
    USE SIGNAL ;
    PORT
      LAYER M4 ;
        RECT  0 6.384 0.192 6.408 ;
    END
  END o[41]
  PIN o[42]
    DIRECTION OUTPUT ;
    USE SIGNAL ;
    PORT
      LAYER M4 ;
        RECT  0 6.48 0.192 6.504 ;
    END
  END o[42]
  PIN o[43]
    DIRECTION OUTPUT ;
    USE SIGNAL ;
    PORT
      LAYER M4 ;
        RECT  0 6.576 0.192 6.6 ;
    END
  END o[43]
  PIN o[44]
    DIRECTION OUTPUT ;
    USE SIGNAL ;
    PORT
      LAYER M4 ;
        RECT  0 6.672 0.192 6.696 ;
    END
  END o[44]
  PIN o[45]
    DIRECTION OUTPUT ;
    USE SIGNAL ;
    PORT
      LAYER M4 ;
        RECT  0 6.768 0.192 6.792 ;
    END
  END o[45]
  PIN o[46]
    DIRECTION OUTPUT ;
    USE SIGNAL ;
    PORT
      LAYER M4 ;
        RECT  0 6.864 0.192 6.888 ;
    END
  END o[46]
  PIN o[47]
    DIRECTION OUTPUT ;
    USE SIGNAL ;
    PORT
      LAYER M4 ;
        RECT  0 7.008 0.192 7.032 ;
    END
  END o[47]
  PIN o[48]
    DIRECTION OUTPUT ;
    USE SIGNAL ;
    PORT
      LAYER M4 ;
        RECT  0 7.104 0.192 7.128 ;
    END
  END o[48]
  PIN o[49]
    DIRECTION OUTPUT ;
    USE SIGNAL ;
    PORT
      LAYER M4 ;
        RECT  0 7.2 0.192 7.224 ;
    END
  END o[49]
  PIN o[4]
    DIRECTION OUTPUT ;
    USE SIGNAL ;
    PORT
      LAYER M4 ;
        RECT  0 2.64 0.192 2.664 ;
    END
  END o[4]
  PIN o[50]
    DIRECTION OUTPUT ;
    USE SIGNAL ;
    PORT
      LAYER M4 ;
        RECT  0 7.296 0.192 7.32 ;
    END
  END o[50]
  PIN o[51]
    DIRECTION OUTPUT ;
    USE SIGNAL ;
    PORT
      LAYER M4 ;
        RECT  0 7.392 0.192 7.416 ;
    END
  END o[51]
  PIN o[52]
    DIRECTION OUTPUT ;
    USE SIGNAL ;
    PORT
      LAYER M4 ;
        RECT  0 7.488 0.192 7.512 ;
    END
  END o[52]
  PIN o[53]
    DIRECTION OUTPUT ;
    USE SIGNAL ;
    PORT
      LAYER M4 ;
        RECT  0 7.584 0.192 7.608 ;
    END
  END o[53]
  PIN o[54]
    DIRECTION OUTPUT ;
    USE SIGNAL ;
    PORT
      LAYER M4 ;
        RECT  0 7.68 0.192 7.704 ;
    END
  END o[54]
  PIN o[55]
    DIRECTION OUTPUT ;
    USE SIGNAL ;
    PORT
      LAYER M4 ;
        RECT  0 7.776 0.192 7.8 ;
    END
  END o[55]
  PIN o[56]
    DIRECTION OUTPUT ;
    USE SIGNAL ;
    PORT
      LAYER M4 ;
        RECT  0 7.92 0.192 7.944 ;
    END
  END o[56]
  PIN o[57]
    DIRECTION OUTPUT ;
    USE SIGNAL ;
    PORT
      LAYER M4 ;
        RECT  0 8.016 0.192 8.04 ;
    END
  END o[57]
  PIN o[58]
    DIRECTION OUTPUT ;
    USE SIGNAL ;
    PORT
      LAYER M4 ;
        RECT  0 8.112 0.192 8.136 ;
    END
  END o[58]
  PIN o[59]
    DIRECTION OUTPUT ;
    USE SIGNAL ;
    PORT
      LAYER M4 ;
        RECT  0 8.208 0.192 8.232 ;
    END
  END o[59]
  PIN o[5]
    DIRECTION OUTPUT ;
    USE SIGNAL ;
    PORT
      LAYER M4 ;
        RECT  0 2.736 0.192 2.76 ;
    END
  END o[5]
  PIN o[60]
    DIRECTION OUTPUT ;
    USE SIGNAL ;
    PORT
      LAYER M4 ;
        RECT  0 8.304 0.192 8.328 ;
    END
  END o[60]
  PIN o[61]
    DIRECTION OUTPUT ;
    USE SIGNAL ;
    PORT
      LAYER M4 ;
        RECT  0 8.4 0.192 8.424 ;
    END
  END o[61]
  PIN o[62]
    DIRECTION OUTPUT ;
    USE SIGNAL ;
    PORT
      LAYER M4 ;
        RECT  0 8.496 0.192 8.52 ;
    END
  END o[62]
  PIN o[63]
    DIRECTION OUTPUT ;
    USE SIGNAL ;
    PORT
      LAYER M4 ;
        RECT  0 8.592 0.192 8.616 ;
    END
  END o[63]
  PIN o[64]
    DIRECTION OUTPUT ;
    USE SIGNAL ;
    PORT
      LAYER M4 ;
        RECT  0 8.688 0.192 8.712 ;
    END
  END o[64]
  PIN o[65]
    DIRECTION OUTPUT ;
    USE SIGNAL ;
    PORT
      LAYER M4 ;
        RECT  0 8.832 0.192 8.856 ;
    END
  END o[65]
  PIN o[66]
    DIRECTION OUTPUT ;
    USE SIGNAL ;
    PORT
      LAYER M4 ;
        RECT  0 8.928 0.192 8.952 ;
    END
  END o[66]
  PIN o[67]
    DIRECTION OUTPUT ;
    USE SIGNAL ;
    PORT
      LAYER M4 ;
        RECT  0 9.024 0.192 9.048 ;
    END
  END o[67]
  PIN o[68]
    DIRECTION OUTPUT ;
    USE SIGNAL ;
    PORT
      LAYER M4 ;
        RECT  0 9.12 0.192 9.144 ;
    END
  END o[68]
  PIN o[69]
    DIRECTION OUTPUT ;
    USE SIGNAL ;
    PORT
      LAYER M4 ;
        RECT  0 9.216 0.192 9.24 ;
    END
  END o[69]
  PIN o[6]
    DIRECTION OUTPUT ;
    USE SIGNAL ;
    PORT
      LAYER M4 ;
        RECT  0 2.832 0.192 2.856 ;
    END
  END o[6]
  PIN o[70]
    DIRECTION OUTPUT ;
    USE SIGNAL ;
    PORT
      LAYER M4 ;
        RECT  0 9.312 0.192 9.336 ;
    END
  END o[70]
  PIN o[71]
    DIRECTION OUTPUT ;
    USE SIGNAL ;
    PORT
      LAYER M4 ;
        RECT  0 9.408 0.192 9.432 ;
    END
  END o[71]
  PIN o[72]
    DIRECTION OUTPUT ;
    USE SIGNAL ;
    PORT
      LAYER M4 ;
        RECT  0 9.504 0.192 9.528 ;
    END
  END o[72]
  PIN o[73]
    DIRECTION OUTPUT ;
    USE SIGNAL ;
    PORT
      LAYER M4 ;
        RECT  0 9.6 0.192 9.624 ;
    END
  END o[73]
  PIN o[74]
    DIRECTION OUTPUT ;
    USE SIGNAL ;
    PORT
      LAYER M4 ;
        RECT  0 9.744 0.192 9.768 ;
    END
  END o[74]
  PIN o[75]
    DIRECTION OUTPUT ;
    USE SIGNAL ;
    PORT
      LAYER M4 ;
        RECT  0 9.84 0.192 9.864 ;
    END
  END o[75]
  PIN o[76]
    DIRECTION OUTPUT ;
    USE SIGNAL ;
    PORT
      LAYER M4 ;
        RECT  0 9.936 0.192 9.96 ;
    END
  END o[76]
  PIN o[77]
    DIRECTION OUTPUT ;
    USE SIGNAL ;
    PORT
      LAYER M4 ;
        RECT  0 10.032 0.192 10.056 ;
    END
  END o[77]
  PIN o[78]
    DIRECTION OUTPUT ;
    USE SIGNAL ;
    PORT
      LAYER M4 ;
        RECT  0 10.128 0.192 10.152 ;
    END
  END o[78]
  PIN o[79]
    DIRECTION OUTPUT ;
    USE SIGNAL ;
    PORT
      LAYER M4 ;
        RECT  0 10.224 0.192 10.248 ;
    END
  END o[79]
  PIN o[7]
    DIRECTION OUTPUT ;
    USE SIGNAL ;
    PORT
      LAYER M4 ;
        RECT  0 2.928 0.192 2.952 ;
    END
  END o[7]
  PIN o[80]
    DIRECTION OUTPUT ;
    USE SIGNAL ;
    PORT
      LAYER M4 ;
        RECT  0 10.32 0.192 10.344 ;
    END
  END o[80]
  PIN o[81]
    DIRECTION OUTPUT ;
    USE SIGNAL ;
    PORT
      LAYER M4 ;
        RECT  0 10.416 0.192 10.44 ;
    END
  END o[81]
  PIN o[82]
    DIRECTION OUTPUT ;
    USE SIGNAL ;
    PORT
      LAYER M4 ;
        RECT  0 10.512 0.192 10.536 ;
    END
  END o[82]
  PIN o[83]
    DIRECTION OUTPUT ;
    USE SIGNAL ;
    PORT
      LAYER M4 ;
        RECT  0 10.656 0.192 10.68 ;
    END
  END o[83]
  PIN o[84]
    DIRECTION OUTPUT ;
    USE SIGNAL ;
    PORT
      LAYER M4 ;
        RECT  0 10.752 0.192 10.776 ;
    END
  END o[84]
  PIN o[85]
    DIRECTION OUTPUT ;
    USE SIGNAL ;
    PORT
      LAYER M4 ;
        RECT  0 10.848 0.192 10.872 ;
    END
  END o[85]
  PIN o[86]
    DIRECTION OUTPUT ;
    USE SIGNAL ;
    PORT
      LAYER M4 ;
        RECT  0 10.944 0.192 10.968 ;
    END
  END o[86]
  PIN o[87]
    DIRECTION OUTPUT ;
    USE SIGNAL ;
    PORT
      LAYER M4 ;
        RECT  0 11.04 0.192 11.064 ;
    END
  END o[87]
  PIN o[88]
    DIRECTION OUTPUT ;
    USE SIGNAL ;
    PORT
      LAYER M4 ;
        RECT  0 11.136 0.192 11.16 ;
    END
  END o[88]
  PIN o[89]
    DIRECTION OUTPUT ;
    USE SIGNAL ;
    PORT
      LAYER M4 ;
        RECT  0 11.232 0.192 11.256 ;
    END
  END o[89]
  PIN o[8]
    DIRECTION OUTPUT ;
    USE SIGNAL ;
    PORT
      LAYER M4 ;
        RECT  0 3.024 0.192 3.048 ;
    END
  END o[8]
  PIN o[90]
    DIRECTION OUTPUT ;
    USE SIGNAL ;
    PORT
      LAYER M4 ;
        RECT  0 11.328 0.192 11.352 ;
    END
  END o[90]
  PIN o[91]
    DIRECTION OUTPUT ;
    USE SIGNAL ;
    PORT
      LAYER M4 ;
        RECT  0 11.424 0.192 11.448 ;
    END
  END o[91]
  PIN o[92]
    DIRECTION OUTPUT ;
    USE SIGNAL ;
    PORT
      LAYER M4 ;
        RECT  0 11.568 0.192 11.592 ;
    END
  END o[92]
  PIN o[93]
    DIRECTION OUTPUT ;
    USE SIGNAL ;
    PORT
      LAYER M4 ;
        RECT  0 11.664 0.192 11.688 ;
    END
  END o[93]
  PIN o[94]
    DIRECTION OUTPUT ;
    USE SIGNAL ;
    PORT
      LAYER M4 ;
        RECT  0 11.76 0.192 11.784 ;
    END
  END o[94]
  PIN o[95]
    DIRECTION OUTPUT ;
    USE SIGNAL ;
    PORT
      LAYER M4 ;
        RECT  0 11.856 0.192 11.88 ;
    END
  END o[95]
  PIN o[96]
    DIRECTION OUTPUT ;
    USE SIGNAL ;
    PORT
      LAYER M4 ;
        RECT  0 11.952 0.192 11.976 ;
    END
  END o[96]
  PIN o[97]
    DIRECTION OUTPUT ;
    USE SIGNAL ;
    PORT
      LAYER M4 ;
        RECT  0 12.048 0.192 12.072 ;
    END
  END o[97]
  PIN o[98]
    DIRECTION OUTPUT ;
    USE SIGNAL ;
    PORT
      LAYER M4 ;
        RECT  0 12.144 0.192 12.168 ;
    END
  END o[98]
  PIN o[99]
    DIRECTION OUTPUT ;
    USE SIGNAL ;
    PORT
      LAYER M4 ;
        RECT  0 12.24 0.192 12.264 ;
    END
  END o[99]
  PIN o[9]
    DIRECTION OUTPUT ;
    USE SIGNAL ;
    PORT
      LAYER M4 ;
        RECT  0 3.12 0.192 3.144 ;
    END
  END o[9]
  PIN rs
    DIRECTION INPUT ;
    USE SIGNAL ;
    PORT
      LAYER M5 ;
        RECT  11.856 32.208 11.88 32.4 ;
    END
  END rs
  PIN VDD
    DIRECTION INOUT ;
    USE POWER ;
    PORT
      LAYER M5 ;
        RECT  13.392 2.151 13.512 30.249 ;
        RECT  10.692 2.151 10.812 30.249 ;
        RECT  7.992 2.151 8.112 30.249 ;
        RECT  5.292 2.151 5.412 30.249 ;
        RECT  2.592 2.151 2.712 30.249 ;
    END
  END VDD
  PIN VSS
    DIRECTION INOUT ;
    USE GROUND ;
    PORT
      LAYER M5 ;
        RECT  13.2 2.137 13.32 30.263 ;
        RECT  10.5 2.137 10.62 30.263 ;
        RECT  7.8 2.137 7.92 30.263 ;
        RECT  5.1 2.137 5.22 30.263 ;
        RECT  2.4 2.137 2.52 30.263 ;
    END
  END VSS
  OBS
    LAYER RVTN ;
     RECT  2.16 2.16 15.12 2.295 ;
     RECT  2.16 2.565 15.12 2.835 ;
     RECT  2.16 3.105 15.12 3.375 ;
     RECT  2.16 3.645 15.12 3.915 ;
     RECT  2.16 4.185 15.12 4.455 ;
     RECT  2.16 4.725 15.12 4.995 ;
     RECT  2.16 5.265 15.12 5.535 ;
     RECT  2.16 5.805 15.12 6.075 ;
     RECT  2.16 6.345 15.12 6.615 ;
     RECT  2.16 6.885 15.12 7.155 ;
     RECT  2.16 7.425 15.12 7.695 ;
     RECT  2.16 7.965 15.12 8.235 ;
     RECT  2.16 8.505 15.12 8.775 ;
     RECT  2.16 9.045 15.12 9.315 ;
     RECT  2.16 9.585 15.12 9.855 ;
     RECT  2.16 10.125 15.12 10.395 ;
     RECT  2.16 10.665 15.12 10.935 ;
     RECT  2.16 11.205 15.12 11.475 ;
     RECT  2.16 11.745 15.12 12.015 ;
     RECT  2.16 12.285 15.12 12.555 ;
     RECT  2.16 12.825 15.12 13.095 ;
     RECT  2.16 13.365 15.12 13.635 ;
     RECT  2.16 13.905 15.12 14.175 ;
     RECT  2.16 14.445 15.12 14.715 ;
     RECT  2.16 14.985 15.12 15.255 ;
     RECT  2.16 15.525 15.12 15.795 ;
     RECT  2.16 16.065 15.12 16.335 ;
     RECT  2.16 16.605 15.12 16.875 ;
     RECT  2.16 17.145 15.12 17.415 ;
     RECT  2.16 17.685 15.12 17.955 ;
     RECT  2.16 18.225 15.12 18.495 ;
     RECT  2.16 18.765 15.12 19.035 ;
     RECT  2.16 19.305 15.12 19.575 ;
     RECT  2.16 19.845 15.12 20.115 ;
     RECT  2.16 20.385 15.12 20.655 ;
     RECT  2.16 20.925 15.12 21.195 ;
     RECT  2.16 21.465 15.12 21.735 ;
     RECT  2.16 22.005 15.12 22.275 ;
     RECT  2.16 22.545 15.12 22.815 ;
     RECT  2.16 23.085 15.12 23.355 ;
     RECT  2.16 23.625 15.12 23.895 ;
     RECT  2.16 24.165 15.12 24.435 ;
     RECT  2.16 24.705 15.12 24.975 ;
     RECT  2.16 25.245 15.12 25.515 ;
     RECT  2.16 25.785 15.12 26.055 ;
     RECT  2.16 26.325 15.12 26.595 ;
     RECT  2.16 26.865 15.12 27.135 ;
     RECT  2.16 27.405 15.12 27.675 ;
     RECT  2.16 27.945 15.12 28.215 ;
     RECT  2.16 28.485 15.12 28.755 ;
     RECT  2.16 29.025 15.12 29.295 ;
     RECT  2.16 29.565 15.12 29.835 ;
     RECT  2.16 30.105 15.12 30.24 ;
    LAYER RVTP ;
     RECT  2.16 2.295 15.12 2.565 ;
     RECT  2.16 2.835 15.12 3.105 ;
     RECT  2.16 3.375 15.12 3.645 ;
     RECT  2.16 3.915 15.12 4.185 ;
     RECT  2.16 4.455 15.12 4.725 ;
     RECT  2.16 4.995 15.12 5.265 ;
     RECT  2.16 5.535 15.12 5.805 ;
     RECT  2.16 6.075 15.12 6.345 ;
     RECT  2.16 6.615 15.12 6.885 ;
     RECT  2.16 7.155 15.12 7.425 ;
     RECT  2.16 7.695 15.12 7.965 ;
     RECT  2.16 8.235 15.12 8.505 ;
     RECT  2.16 8.775 15.12 9.045 ;
     RECT  2.16 9.315 15.12 9.585 ;
     RECT  2.16 9.855 15.12 10.125 ;
     RECT  2.16 10.395 15.12 10.665 ;
     RECT  2.16 10.935 15.12 11.205 ;
     RECT  2.16 11.475 15.12 11.745 ;
     RECT  2.16 12.015 15.12 12.285 ;
     RECT  2.16 12.555 15.12 12.825 ;
     RECT  2.16 13.095 15.12 13.365 ;
     RECT  2.16 13.635 15.12 13.905 ;
     RECT  2.16 14.175 15.12 14.445 ;
     RECT  2.16 14.715 15.12 14.985 ;
     RECT  2.16 15.255 15.12 15.525 ;
     RECT  2.16 15.795 15.12 16.065 ;
     RECT  2.16 16.335 15.12 16.605 ;
     RECT  2.16 16.875 15.12 17.145 ;
     RECT  2.16 17.415 15.12 17.685 ;
     RECT  2.16 17.955 15.12 18.225 ;
     RECT  2.16 18.495 15.12 18.765 ;
     RECT  2.16 19.035 15.12 19.305 ;
     RECT  2.16 19.575 15.12 19.845 ;
     RECT  2.16 20.115 15.12 20.385 ;
     RECT  2.16 20.655 15.12 20.925 ;
     RECT  2.16 21.195 15.12 21.465 ;
     RECT  2.16 21.735 15.12 22.005 ;
     RECT  2.16 22.275 15.12 22.545 ;
     RECT  2.16 22.815 15.12 23.085 ;
     RECT  2.16 23.355 15.12 23.625 ;
     RECT  2.16 23.895 15.12 24.165 ;
     RECT  2.16 24.435 15.12 24.705 ;
     RECT  2.16 24.975 15.12 25.245 ;
     RECT  2.16 25.515 15.12 25.785 ;
     RECT  2.16 26.055 15.12 26.325 ;
     RECT  2.16 26.595 15.12 26.865 ;
     RECT  2.16 27.135 15.12 27.405 ;
     RECT  2.16 27.675 15.12 27.945 ;
     RECT  2.16 28.215 15.12 28.485 ;
     RECT  2.16 28.755 15.12 29.025 ;
     RECT  2.16 29.295 15.12 29.565 ;
     RECT  2.16 29.835 15.12 30.105 ;
    LAYER M1 ;
     RECT  2.16 2.151 15.12 30.249 ;
    LAYER M2 ;
     RECT  0.211 10.791 0.311 10.809 ;
     RECT  0.211 25.452 0.311 25.47 ;
     RECT  0.211 19.656 0.535 19.674 ;
     RECT  0.211 22.788 0.535 22.806 ;
     RECT  0.499 27.342 0.535 27.864 ;
     RECT  0.535 16.416 0.635 17.946 ;
     RECT  0.635 16.416 1.175 17.064 ;
     RECT  0.535 25.056 1.183 25.074 ;
     RECT  1.183 24.912 1.211 25.074 ;
     RECT  1.975 3.006 2.16 3.024 ;
     RECT  0.535 7.938 2.16 7.956 ;
     RECT  1.975 10.296 2.16 10.314 ;
     RECT  0.535 11.376 2.16 11.934 ;
     RECT  0.535 13.536 2.16 13.554 ;
     RECT  1.175 16.416 2.16 16.902 ;
     RECT  0.635 17.928 2.16 17.946 ;
     RECT  0.535 19.35 2.16 19.674 ;
     RECT  0.535 21.438 2.16 22.914 ;
     RECT  1.211 24.912 2.16 24.93 ;
     RECT  0.535 26.676 2.16 27.864 ;
     RECT  2.16 2.151 3.199 30.249 ;
     RECT  3.199 2.151 3.523 30.294 ;
     RECT  3.523 2.106 4.567 30.294 ;
     RECT  4.567 2.034 6.979 30.294 ;
     RECT  6.979 2.034 7.699 30.33 ;
     RECT  7.699 2.034 7.951 30.366 ;
     RECT  7.951 1.998 8.015 30.366 ;
     RECT  8.015 1.998 8.195 30.33 ;
     RECT  8.195 1.998 13.091 30.294 ;
     RECT  13.091 1.998 15.12 30.249 ;
     RECT  15.12 1.998 15.431 7.218 ;
     RECT  15.12 8.748 15.431 13.32 ;
     RECT  15.12 14.148 15.431 14.238 ;
     RECT  15.12 15.03 15.431 23.922 ;
     RECT  15.12 25.29 15.431 29.556 ;
     RECT  15.431 5.85 15.467 6.336 ;
     RECT  15.431 14.148 15.467 14.166 ;
     RECT  15.431 15.03 15.467 18.45 ;
     RECT  15.431 20.16 15.467 21.222 ;
     RECT  15.431 25.29 15.467 27.36 ;
     RECT  15.431 7.2 15.503 7.218 ;
     RECT  15.431 1.998 16.007 3.402 ;
     RECT  15.431 10.908 16.007 12.51 ;
     RECT  15.467 16.074 16.007 18.45 ;
     RECT  15.431 22.626 16.007 23.346 ;
     RECT  16.007 3.384 16.547 3.402 ;
     RECT  15.431 4.23 16.547 4.248 ;
     RECT  15.431 9.09 16.547 9.846 ;
     RECT  16.007 10.908 16.547 11.304 ;
     RECT  16.007 12.492 16.547 12.51 ;
     RECT  15.431 13.302 16.547 13.32 ;
     RECT  16.007 16.074 16.547 17.1 ;
     RECT  16.007 18.036 16.547 18.45 ;
     RECT  15.431 19.35 16.547 19.368 ;
     RECT  15.467 20.16 16.547 20.178 ;
     RECT  15.467 21.204 16.547 21.222 ;
     RECT  16.007 23.328 16.547 23.346 ;
     RECT  15.467 25.29 16.547 25.74 ;
     RECT  16.007 1.998 16.583 2.322 ;
     RECT  15.467 26.802 16.583 27.36 ;
     RECT  16.583 2.07 16.619 2.322 ;
     RECT  15.467 5.85 16.619 5.868 ;
     RECT  16.619 2.106 17.023 2.322 ;
     RECT  15.467 15.03 17.059 15.048 ;
     RECT  15.431 29.268 17.059 29.286 ;
     RECT  17.023 2.106 17.123 2.862 ;
     RECT  15.431 28.188 17.123 28.206 ;
     RECT  17.059 4.392 17.159 5.22 ;
     RECT  17.059 6.354 17.159 6.372 ;
     RECT  17.059 8.136 17.159 8.154 ;
     RECT  17.059 10.872 17.159 10.89 ;
     RECT  17.059 12.06 17.159 12.078 ;
     RECT  17.059 14.994 17.159 15.516 ;
     RECT  16.547 16.578 17.159 16.596 ;
     RECT  17.023 18.666 17.159 19.062 ;
     RECT  17.059 21.942 17.159 22.644 ;
     RECT  17.059 24.678 17.159 24.696 ;
     RECT  17.023 26.37 17.159 26.784 ;
     RECT  17.059 29.268 17.159 29.628 ;
    LAYER M3 ;
     RECT  10.26 2.029 10.278 2.059 ;
     RECT  7.956 1.993 7.974 2.065 ;
     RECT  16.56 1.993 16.578 2.065 ;
     RECT  3.276 2.059 3.294 2.101 ;
     RECT  4.572 2.029 4.59 2.101 ;
     RECT  7.956 2.065 8.37 2.101 ;
     RECT  16.56 2.065 16.614 2.101 ;
     RECT  7.956 2.101 8.514 2.143 ;
     RECT  2.415 2.143 2.505 2.191 ;
     RECT  10.26 2.059 10.71 2.191 ;
     RECT  13.215 2.143 13.305 2.203 ;
     RECT  13.104 2.203 13.305 2.227 ;
     RECT  3.276 2.101 3.546 2.263 ;
     RECT  4.572 2.101 5.274 2.263 ;
     RECT  12.816 2.227 13.305 2.263 ;
     RECT  16.56 2.101 17.118 2.293 ;
     RECT  9.936 2.191 10.71 2.299 ;
     RECT  3.276 2.263 5.274 2.335 ;
     RECT  12.816 2.263 13.806 2.335 ;
     RECT  2.304 2.191 2.505 2.347 ;
     RECT  7.815 2.143 8.514 2.347 ;
     RECT  9.504 2.299 11.322 2.347 ;
     RECT  12.816 2.335 13.95 2.371 ;
     RECT  15.408 2.203 15.426 2.371 ;
     RECT  1.98 2.347 2.505 2.413 ;
     RECT  3.276 2.335 5.958 2.413 ;
     RECT  12.24 2.371 13.95 2.489 ;
     RECT  14.724 2.371 15.426 2.489 ;
     RECT  1.98 2.413 5.958 2.569 ;
     RECT  7.092 2.347 11.322 2.569 ;
     RECT  12.24 2.489 13.914 2.569 ;
     RECT  1.98 2.569 6.282 2.759 ;
     RECT  14.832 2.489 15.426 2.803 ;
     RECT  16.524 2.293 17.118 2.803 ;
     RECT  3.744 2.759 6.282 2.813 ;
     RECT  1.98 2.759 2.898 2.831 ;
     RECT  3.744 2.813 5.67 2.861 ;
     RECT  14.832 2.803 17.118 2.867 ;
     RECT  7.092 2.569 13.914 2.875 ;
     RECT  14.832 2.867 17.046 2.903 ;
     RECT  6.516 2.875 13.914 2.912 ;
     RECT  15.984 2.903 17.046 2.957 ;
     RECT  3.96 2.861 5.67 3.029 ;
     RECT  16.524 2.957 17.046 3.407 ;
     RECT  6.84 2.912 13.914 3.437 ;
     RECT  7.38 3.437 13.914 3.451 ;
     RECT  3.96 3.029 4.374 3.569 ;
     RECT  1.98 2.831 2.862 3.64 ;
     RECT  3.96 3.569 4.23 3.64 ;
     RECT  14.832 2.903 14.958 3.643 ;
     RECT  5.115 3.029 5.67 3.649 ;
     RECT  14.832 3.643 14.994 3.739 ;
     RECT  1.98 3.64 4.23 3.773 ;
     RECT  5.115 3.649 5.886 3.811 ;
     RECT  14.832 3.739 15.102 3.835 ;
     RECT  4.968 3.811 5.958 3.92 ;
     RECT  5.115 3.92 5.958 4.153 ;
     RECT  17.028 3.407 17.046 4.171 ;
     RECT  16.524 4.171 17.046 4.253 ;
     RECT  5.115 4.153 6.138 4.261 ;
     RECT  5.115 4.261 6.21 4.351 ;
     RECT  17.028 4.253 17.046 4.363 ;
     RECT  17.028 4.363 17.082 4.387 ;
     RECT  5.115 4.351 6.282 4.459 ;
     RECT  7.38 3.451 14.058 4.459 ;
     RECT  5.115 4.459 14.058 4.487 ;
     RECT  2.304 3.773 4.23 4.621 ;
     RECT  0.252 4.555 0.27 4.733 ;
     RECT  2.304 4.621 4.374 4.747 ;
     RECT  5.115 4.487 5.85 4.747 ;
     RECT  6.804 4.487 14.058 4.801 ;
     RECT  14.832 3.835 15.426 4.801 ;
     RECT  6.804 4.801 15.426 4.919 ;
     RECT  0.288 4.843 0.414 4.973 ;
     RECT  0.288 4.973 0.306 5.069 ;
     RECT  2.304 4.747 5.85 5.225 ;
     RECT  14.832 4.919 15.426 5.261 ;
     RECT  17.028 4.387 17.154 5.261 ;
     RECT  17.028 5.261 17.046 5.309 ;
     RECT  5.004 5.225 5.85 5.431 ;
     RECT  6.804 4.919 13.914 5.431 ;
     RECT  2.304 5.225 4.23 5.459 ;
     RECT  5.004 5.431 13.914 5.773 ;
     RECT  14.832 5.261 14.994 5.773 ;
     RECT  2.304 5.459 4.194 5.947 ;
     RECT  2.268 5.947 4.194 5.999 ;
     RECT  5.004 5.773 14.994 6.187 ;
     RECT  2.304 5.999 4.194 6.241 ;
     RECT  5.004 6.187 15.426 6.241 ;
     RECT  2.304 6.241 15.426 6.283 ;
     RECT  16.524 5.659 16.614 6.331 ;
     RECT  2.304 6.283 15.462 6.341 ;
     RECT  16.524 6.331 17.154 6.377 ;
     RECT  16.524 6.377 17.082 6.413 ;
     RECT  2.304 6.341 15.426 6.575 ;
     RECT  0.252 6.475 0.27 6.653 ;
     RECT  6.264 6.575 15.426 6.701 ;
     RECT  2.304 6.575 5.397 6.845 ;
     RECT  6.336 6.701 15.426 6.845 ;
     RECT  7.308 6.845 15.426 7.099 ;
     RECT  7.308 7.099 15.498 7.223 ;
     RECT  6.336 6.845 6.462 7.349 ;
     RECT  2.304 6.845 3.078 7.579 ;
     RECT  2.268 7.579 3.078 7.591 ;
     RECT  3.816 6.845 5.397 7.591 ;
     RECT  7.308 7.223 14.886 7.627 ;
     RECT  7.272 7.627 14.886 7.889 ;
     RECT  2.268 7.591 5.397 7.933 ;
     RECT  7.272 7.889 13.914 7.933 ;
     RECT  2.196 7.933 5.397 7.961 ;
     RECT  16.524 6.413 16.578 7.997 ;
     RECT  0.54 7.933 0.558 8.045 ;
     RECT  17.064 8.107 17.082 8.131 ;
     RECT  17.064 8.131 17.154 8.159 ;
     RECT  17.136 8.159 17.154 8.189 ;
     RECT  7.2 7.933 13.914 8.251 ;
     RECT  2.196 7.961 4.05 8.443 ;
     RECT  4.824 7.961 5.397 8.525 ;
     RECT  6.768 8.251 13.914 8.54 ;
     RECT  5.115 8.525 5.397 8.545 ;
     RECT  5.115 8.545 5.742 8.581 ;
     RECT  5.115 8.581 5.814 8.671 ;
     RECT  6.804 8.54 13.914 8.671 ;
     RECT  14.832 7.889 14.886 8.671 ;
     RECT  6.804 8.671 14.886 8.731 ;
     RECT  6.804 8.731 15.426 8.765 ;
     RECT  6.804 8.765 13.842 8.771 ;
     RECT  14.58 8.765 15.426 8.771 ;
     RECT  1.98 8.443 4.05 8.827 ;
     RECT  5.115 8.671 5.85 8.843 ;
     RECT  7.056 8.771 13.842 8.969 ;
     RECT  14.58 8.771 14.958 9.041 ;
     RECT  7.056 8.969 11.646 9.053 ;
     RECT  14.832 9.041 14.958 9.101 ;
     RECT  1.98 8.827 4.302 9.283 ;
     RECT  5.115 8.843 5.814 9.283 ;
     RECT  1.98 9.283 5.814 9.341 ;
     RECT  1.98 9.341 4.014 9.437 ;
     RECT  7.38 9.053 11.646 9.751 ;
     RECT  12.492 8.969 13.842 9.751 ;
     RECT  7.38 9.751 13.842 9.787 ;
     RECT  7.344 9.787 13.842 9.823 ;
     RECT  5.115 9.341 5.814 9.835 ;
     RECT  6.84 9.823 13.842 9.835 ;
     RECT  14.832 9.101 14.886 9.835 ;
     RECT  16.524 9.019 16.542 9.869 ;
     RECT  5.115 9.835 13.842 9.895 ;
     RECT  14.832 9.835 14.958 9.895 ;
     RECT  5.115 9.895 14.958 10.109 ;
     RECT  2.304 9.437 4.014 10.123 ;
     RECT  2.304 10.123 4.266 10.219 ;
     RECT  1.98 10.219 4.266 10.229 ;
     RECT  7.2 10.109 14.958 10.229 ;
     RECT  7.632 10.229 14.958 10.267 ;
     RECT  1.98 10.229 4.122 10.319 ;
     RECT  2.304 10.319 4.122 10.445 ;
     RECT  7.632 10.267 15.426 10.697 ;
     RECT  16.56 10.603 16.578 10.747 ;
     RECT  0.252 10.603 0.27 10.78 ;
     RECT  16.524 10.747 16.578 10.843 ;
     RECT  16.524 10.843 17.082 10.867 ;
     RECT  16.524 10.867 17.154 10.925 ;
     RECT  5.115 10.109 6.282 11.011 ;
     RECT  16.524 10.925 16.578 11.021 ;
     RECT  0.216 10.78 0.306 11.069 ;
     RECT  3.996 10.445 4.122 11.101 ;
     RECT  5.115 11.011 6.858 11.101 ;
     RECT  7.632 10.697 14.922 11.131 ;
     RECT  2.304 10.445 3.186 11.209 ;
     RECT  3.996 11.101 6.858 11.209 ;
     RECT  2.304 11.209 6.858 11.245 ;
     RECT  7.596 11.131 14.922 11.245 ;
     RECT  16.524 11.021 16.542 11.315 ;
     RECT  2.304 11.245 14.922 11.563 ;
     RECT  2.304 11.563 15.426 11.813 ;
     RECT  0.54 11.371 0.558 11.851 ;
     RECT  0.54 11.851 1.278 11.981 ;
     RECT  2.304 11.813 14.886 11.981 ;
     RECT  15.984 11.821 16.002 12.029 ;
     RECT  17.136 12.043 17.154 12.055 ;
     RECT  0.54 11.981 0.558 12.077 ;
     RECT  2.304 11.981 5.814 12.077 ;
     RECT  17.064 12.055 17.154 12.083 ;
     RECT  17.064 12.083 17.082 12.125 ;
     RECT  6.624 11.981 14.886 12.479 ;
     RECT  2.304 12.077 5.397 12.515 ;
     RECT  6.696 12.479 14.886 12.551 ;
     RECT  0.252 12.523 0.27 12.701 ;
     RECT  7.272 12.551 14.886 12.763 ;
     RECT  7.272 12.763 14.922 12.793 ;
     RECT  3.6 12.515 5.397 12.797 ;
     RECT  3.996 12.797 5.397 12.821 ;
     RECT  4.176 12.821 5.397 12.991 ;
     RECT  2.304 12.515 2.697 13.019 ;
     RECT  7.272 12.793 15.426 13.019 ;
     RECT  7.272 13.019 13.554 13.085 ;
     RECT  4.176 12.991 5.85 13.091 ;
     RECT  2.415 13.019 2.697 13.261 ;
     RECT  2.415 13.261 2.754 13.291 ;
     RECT  7.38 13.085 13.554 13.325 ;
     RECT  16.524 12.283 16.542 13.325 ;
     RECT  0.324 13.339 0.342 13.483 ;
     RECT  0.252 13.483 0.342 13.531 ;
     RECT  1.152 13.339 1.17 13.531 ;
     RECT  14.364 13.019 15.426 13.559 ;
     RECT  7.416 13.325 13.554 13.565 ;
     RECT  4.176 13.091 5.397 13.603 ;
     RECT  0.252 13.531 1.17 13.661 ;
     RECT  2.415 13.291 2.826 13.771 ;
     RECT  2.304 13.771 2.826 13.801 ;
     RECT  0.54 13.661 1.17 13.901 ;
     RECT  14.58 13.559 15.426 14.011 ;
     RECT  1.152 13.901 1.17 14.059 ;
     RECT  2.304 13.801 2.898 14.071 ;
     RECT  3.996 13.603 5.397 14.071 ;
     RECT  6.264 13.441 6.57 14.071 ;
     RECT  7.416 13.565 11.79 14.071 ;
     RECT  12.528 13.565 13.554 14.071 ;
     RECT  14.58 14.011 15.462 14.099 ;
     RECT  14.832 14.099 15.462 14.171 ;
     RECT  1.152 14.059 1.278 14.237 ;
     RECT  14.832 14.171 15.426 14.243 ;
     RECT  6.264 14.071 11.79 14.251 ;
     RECT  2.304 14.071 5.397 14.381 ;
     RECT  6.228 14.251 11.79 14.413 ;
     RECT  12.528 14.071 13.842 14.413 ;
     RECT  2.304 14.381 2.697 14.521 ;
     RECT  6.228 14.413 13.842 14.521 ;
     RECT  3.42 14.381 5.397 14.611 ;
     RECT  6.228 14.521 14.058 14.611 ;
     RECT  2.268 14.521 2.697 14.621 ;
     RECT  3.42 14.611 14.058 14.639 ;
     RECT  16.56 14.395 16.578 14.731 ;
     RECT  3.42 14.639 4.086 14.783 ;
     RECT  14.832 14.243 14.922 14.953 ;
     RECT  16.524 14.731 16.578 14.971 ;
     RECT  16.524 14.971 17.154 15.053 ;
     RECT  14.796 14.953 14.922 15.089 ;
     RECT  14.832 15.089 14.922 15.115 ;
     RECT  5.115 14.639 14.058 15.179 ;
     RECT  14.832 15.115 15.426 15.25 ;
     RECT  2.304 14.621 2.697 15.295 ;
     RECT  3.42 14.783 3.906 15.295 ;
     RECT  2.304 15.295 3.906 15.529 ;
     RECT  16.56 15.053 17.154 15.533 ;
     RECT  14.832 15.25 15.462 15.593 ;
     RECT  2.304 15.529 4.374 15.691 ;
     RECT  1.152 15.739 1.17 15.917 ;
     RECT  16.56 15.533 16.578 16.069 ;
     RECT  14.832 15.593 15.426 16.141 ;
     RECT  2.268 15.691 4.374 16.259 ;
     RECT  2.304 16.259 4.374 16.303 ;
     RECT  5.115 15.179 13.914 16.303 ;
     RECT  14.76 16.141 15.426 16.303 ;
     RECT  0.252 16.267 0.27 16.411 ;
     RECT  0.252 16.411 0.558 16.445 ;
     RECT  16.524 16.069 16.578 16.555 ;
     RECT  16.524 16.555 17.082 16.573 ;
     RECT  16.524 16.573 17.154 16.637 ;
     RECT  0.54 16.445 0.558 16.879 ;
     RECT  0.54 16.879 1.17 17.069 ;
     RECT  16.524 16.637 16.578 17.117 ;
     RECT  2.304 16.303 15.426 17.213 ;
     RECT  0.54 17.069 0.63 17.249 ;
     RECT  5.115 17.213 15.426 17.653 ;
     RECT  16.524 17.117 16.542 17.653 ;
     RECT  5.115 17.653 16.542 17.693 ;
     RECT  5.115 17.693 15.426 17.753 ;
     RECT  2.304 17.213 4.23 17.761 ;
     RECT  2.268 17.761 4.23 17.885 ;
     RECT  5.115 17.753 13.914 18.184 ;
     RECT  5.04 18.184 13.914 18.221 ;
     RECT  2.304 17.885 4.23 18.229 ;
     RECT  5.04 18.221 13.842 18.229 ;
     RECT  0.54 17.249 0.558 18.269 ;
     RECT  16.524 17.693 16.542 18.455 ;
     RECT  17.028 18.619 17.082 18.661 ;
     RECT  2.304 18.229 13.842 18.715 ;
     RECT  1.98 18.715 13.842 18.797 ;
     RECT  14.688 17.753 15.426 18.841 ;
     RECT  1.98 18.797 3.078 18.893 ;
     RECT  17.028 18.661 17.154 19.085 ;
     RECT  3.816 18.797 13.842 19.111 ;
     RECT  14.58 18.841 15.426 19.111 ;
     RECT  3.816 19.111 15.426 19.301 ;
     RECT  0.54 19.345 0.558 19.565 ;
     RECT  2.304 18.893 3.078 19.571 ;
     RECT  3.96 19.301 15.426 19.643 ;
     RECT  0.216 19.651 0.234 19.709 ;
     RECT  6.336 19.643 15.426 19.769 ;
     RECT  6.336 19.769 13.842 19.853 ;
     RECT  3.96 19.643 5.49 20.083 ;
     RECT  16.524 19.195 16.542 20.183 ;
     RECT  2.304 19.571 2.826 20.317 ;
     RECT  3.816 20.083 5.49 20.317 ;
     RECT  6.516 19.853 13.842 20.333 ;
     RECT  2.304 20.317 5.49 20.443 ;
     RECT  2.268 20.443 5.49 20.489 ;
     RECT  14.832 19.769 15.426 20.539 ;
     RECT  6.516 20.333 11.142 20.615 ;
     RECT  6.516 20.615 10.962 20.623 ;
     RECT  14.832 20.539 15.462 20.723 ;
     RECT  11.952 20.333 13.842 20.957 ;
     RECT  0.252 20.923 0.27 21.101 ;
     RECT  2.304 20.489 5.49 21.115 ;
     RECT  6.228 20.623 10.962 21.115 ;
     RECT  12.276 20.957 13.842 21.361 ;
     RECT  1.152 21.259 1.17 21.433 ;
     RECT  12.276 21.361 13.914 21.451 ;
     RECT  14.832 20.723 15.426 21.451 ;
     RECT  2.304 21.115 10.962 21.499 ;
     RECT  2.304 21.499 10.998 21.505 ;
     RECT  2.304 21.505 11.502 21.659 ;
     RECT  16.524 20.923 16.542 21.725 ;
     RECT  2.304 21.659 11.394 21.731 ;
     RECT  0.54 21.433 1.17 22.109 ;
     RECT  12.276 21.451 15.426 22.205 ;
     RECT  12.348 22.205 15.426 22.253 ;
     RECT  14.724 22.253 15.426 22.307 ;
     RECT  2.304 21.731 2.697 22.513 ;
     RECT  14.796 22.307 15.426 22.621 ;
     RECT  17.064 21.928 17.154 22.649 ;
     RECT  17.064 22.649 17.082 22.685 ;
     RECT  1.98 22.513 2.697 22.733 ;
     RECT  14.796 22.621 16.002 22.739 ;
     RECT  0.54 22.109 0.558 22.78 ;
     RECT  14.832 22.739 16.002 22.811 ;
     RECT  0.216 22.78 0.558 22.925 ;
     RECT  15.984 22.811 16.002 22.925 ;
     RECT  2.304 22.733 2.697 22.981 ;
     RECT  3.564 21.731 11.394 22.981 ;
     RECT  12.348 22.253 13.698 22.981 ;
     RECT  2.304 22.981 13.734 23.083 ;
     RECT  2.304 23.083 13.842 23.189 ;
     RECT  0.54 22.925 0.558 23.453 ;
     RECT  2.304 23.189 2.934 23.563 ;
     RECT  14.832 22.811 14.958 23.629 ;
     RECT  3.708 23.189 13.842 23.701 ;
     RECT  14.832 23.629 14.994 23.707 ;
     RECT  1.98 23.563 2.934 23.741 ;
     RECT  1.152 23.755 1.17 23.803 ;
     RECT  14.832 23.707 15.426 23.927 ;
     RECT  1.152 23.803 1.278 23.933 ;
     RECT  16.524 23.275 16.542 24.029 ;
     RECT  3.708 23.701 13.914 24.125 ;
     RECT  4.824 24.125 13.914 24.205 ;
     RECT  14.832 23.927 15.066 24.205 ;
     RECT  2.304 23.741 2.934 24.241 ;
     RECT  3.708 24.125 4.05 24.241 ;
     RECT  4.824 24.205 15.066 24.503 ;
     RECT  6.84 24.503 15.066 24.509 ;
     RECT  2.304 24.241 4.05 24.653 ;
     RECT  17.064 24.664 17.154 24.701 ;
     RECT  17.064 24.701 17.082 24.749 ;
     RECT  0.252 24.523 0.27 24.811 ;
     RECT  2.415 24.653 4.05 24.871 ;
     RECT  4.824 24.503 5.85 24.871 ;
     RECT  1.152 23.933 1.17 24.907 ;
     RECT  16.596 24.955 16.614 25.003 ;
     RECT  12.564 24.509 14.886 25.007 ;
     RECT  0.252 24.811 0.414 25.051 ;
     RECT  1.152 24.907 1.206 25.051 ;
     RECT  0.252 25.051 1.206 25.079 ;
     RECT  2.415 24.871 5.85 25.079 ;
     RECT  16.524 25.003 16.614 25.133 ;
     RECT  0.252 25.079 0.558 25.181 ;
     RECT  16.524 25.133 16.542 25.195 ;
     RECT  6.84 24.509 11.754 25.249 ;
     RECT  12.564 25.007 13.878 25.249 ;
     RECT  3.852 25.079 5.85 25.285 ;
     RECT  6.84 25.249 13.878 25.285 ;
     RECT  14.832 25.007 14.886 25.291 ;
     RECT  15.984 25.195 16.542 25.291 ;
     RECT  0.252 25.181 0.306 25.339 ;
     RECT  14.832 25.291 16.542 25.349 ;
     RECT  0.216 25.339 0.306 25.484 ;
     RECT  0.252 25.484 0.27 25.661 ;
     RECT  16.524 25.349 16.542 25.757 ;
     RECT  2.415 25.079 2.754 25.819 ;
     RECT  3.852 25.285 13.878 25.859 ;
     RECT  2.304 25.819 2.754 25.861 ;
     RECT  2.268 25.861 3.078 26.011 ;
     RECT  1.98 26.011 3.078 26.059 ;
     RECT  3.852 25.859 5.454 26.059 ;
     RECT  1.98 26.059 5.454 26.189 ;
     RECT  6.264 25.859 13.878 26.221 ;
     RECT  14.832 25.349 15.426 26.251 ;
     RECT  14.832 26.251 15.462 26.321 ;
     RECT  6.264 26.221 13.95 26.347 ;
     RECT  17.028 26.347 17.082 26.365 ;
     RECT  14.832 26.321 15.426 26.393 ;
     RECT  6.264 26.347 14.058 26.401 ;
     RECT  14.832 26.393 14.958 26.401 ;
     RECT  1.152 26.299 1.17 26.443 ;
     RECT  6.264 26.401 14.958 26.627 ;
     RECT  17.028 26.365 17.154 26.635 ;
     RECT  1.152 26.443 1.278 26.671 ;
     RECT  6.264 26.627 13.914 26.761 ;
     RECT  2.304 26.189 5.454 26.797 ;
     RECT  6.192 26.761 13.914 26.797 ;
     RECT  16.524 26.635 17.154 26.813 ;
     RECT  0.54 26.671 1.278 26.971 ;
     RECT  2.304 26.797 13.914 27.059 ;
     RECT  0.54 26.971 1.386 27.101 ;
     RECT  0.54 27.101 1.278 27.197 ;
     RECT  0.54 27.197 1.17 27.337 ;
     RECT  6.12 27.059 13.914 27.409 ;
     RECT  14.832 26.627 14.958 27.409 ;
     RECT  16.524 26.813 17.118 27.533 ;
     RECT  6.12 27.409 14.958 27.643 ;
     RECT  0.504 27.337 1.17 27.779 ;
     RECT  2.304 27.059 5.397 27.832 ;
     RECT  6.12 27.643 15.426 27.832 ;
     RECT  0.504 27.779 0.558 28.013 ;
     RECT  0.504 28.013 0.522 28.109 ;
     RECT  17.1 27.533 17.118 28.211 ;
     RECT  2.304 27.832 15.426 28.283 ;
     RECT  2.304 28.283 14.094 28.679 ;
     RECT  1.26 28.555 1.278 28.733 ;
     RECT  2.304 28.679 11.646 28.733 ;
     RECT  4.572 28.733 11.646 28.823 ;
     RECT  16.524 28.987 16.542 29.035 ;
     RECT  16.524 29.035 16.614 29.227 ;
     RECT  0.252 29.083 0.27 29.261 ;
     RECT  16.524 29.227 17.154 29.291 ;
     RECT  2.304 28.733 3.798 29.363 ;
     RECT  4.572 28.823 11.502 29.461 ;
     RECT  4.32 29.461 11.502 29.501 ;
     RECT  4.464 29.501 11.502 29.561 ;
     RECT  14.832 28.283 15.426 29.561 ;
     RECT  12.42 28.679 14.094 29.605 ;
     RECT  14.832 29.561 14.958 29.605 ;
     RECT  2.304 29.363 3.582 29.633 ;
     RECT  17.064 29.291 17.154 29.633 ;
     RECT  4.68 29.561 11.502 29.641 ;
     RECT  12.42 29.605 14.958 29.641 ;
     RECT  4.68 29.641 14.958 29.645 ;
     RECT  17.136 29.633 17.154 29.645 ;
     RECT  0.288 29.707 0.414 29.837 ;
     RECT  14.22 29.645 14.958 29.837 ;
     RECT  4.68 29.645 13.497 29.903 ;
     RECT  5.004 29.903 13.497 29.987 ;
     RECT  5.004 29.987 13.305 30.029 ;
     RECT  14.256 29.837 14.958 30.029 ;
     RECT  0.288 29.837 0.306 30.077 ;
     RECT  5.004 30.029 5.205 30.077 ;
     RECT  14.256 30.029 14.85 30.077 ;
     RECT  6.156 30.029 13.305 30.101 ;
     RECT  12.888 30.101 13.305 30.173 ;
     RECT  2.304 29.633 3.402 30.209 ;
     RECT  11.988 30.101 12.006 30.209 ;
     RECT  2.304 30.209 3.222 30.221 ;
     RECT  6.3 30.101 10.854 30.221 ;
     RECT  14.256 30.077 14.274 30.221 ;
     RECT  2.415 30.221 3.222 30.257 ;
     RECT  5.115 30.077 5.205 30.257 ;
     RECT  10.515 30.221 10.854 30.257 ;
     RECT  13.068 30.173 13.305 30.257 ;
     RECT  6.984 30.221 9.774 30.269 ;
     RECT  3.204 30.257 3.222 30.299 ;
     RECT  13.068 30.257 13.086 30.299 ;
     RECT  6.984 30.269 8.19 30.335 ;
     RECT  9.756 30.269 9.774 30.365 ;
     RECT  10.836 30.257 10.854 30.365 ;
     RECT  7.704 30.335 8.01 30.371 ;
     RECT  5.4 32.155 5.706 32.268 ;
     RECT  5.688 32.268 5.706 32.285 ;
    LAYER M4 ;
     RECT  0.156 2.208 2.408 30.216 ;
     RECT  2.408 2.148 2.512 30.252 ;
     RECT  2.512 2.148 3.265 30.12 ;
     RECT  3.265 2.064 3.269 30.12 ;
     RECT  3.269 2.064 3.377 30.072 ;
     RECT  3.377 2.064 3.413 29.832 ;
     RECT  3.413 2.064 4.025 29.496 ;
     RECT  4.025 2.064 4.993 28.2 ;
     RECT  4.025 29.232 4.993 29.496 ;
     RECT  4.993 2.064 5.108 30.072 ;
     RECT  5.108 2.064 5.212 30.252 ;
     RECT  5.389 32.16 5.677 32.184 ;
     RECT  5.677 32.16 5.717 32.28 ;
     RECT  5.212 2.064 6.289 29.982 ;
     RECT  6.289 2.064 7.808 30.216 ;
     RECT  7.808 2.064 8.773 30.252 ;
     RECT  5.717 32.256 9.731 32.28 ;
     RECT  8.773 2.064 9.745 30.264 ;
     RECT  9.745 2.064 10.721 30.36 ;
     RECT  10.721 2.208 10.865 30.36 ;
     RECT  10.865 2.208 11.891 30.216 ;
     RECT  11.891 2.208 13.208 30.168 ;
     RECT  13.208 2.148 13.312 30.252 ;
     RECT  13.312 2.418 13.504 30.216 ;
     RECT  13.504 2.544 15.397 30.216 ;
     RECT  15.397 2.208 17.1 30.216 ;
     RECT  17.1 4.416 17.165 5.256 ;
     RECT  17.1 6.336 17.165 6.36 ;
     RECT  17.1 8.16 17.165 8.184 ;
     RECT  17.1 10.896 17.165 10.92 ;
     RECT  17.1 12.048 17.165 12.072 ;
     RECT  17.1 14.976 17.165 15.528 ;
     RECT  17.1 16.608 17.165 16.632 ;
     RECT  17.1 18.672 17.165 19.08 ;
     RECT  17.1 21.936 17.165 22.632 ;
     RECT  17.1 24.672 17.165 24.696 ;
     RECT  17.1 26.4 17.165 26.808 ;
     RECT  17.1 29.232 17.165 29.64 ;
    LAYER M5 ;
     RECT  2.4 2.137 2.52 2.151 ;
     RECT  5.1 2.137 5.22 2.151 ;
     RECT  7.8 2.137 7.92 2.151 ;
     RECT  10.5 2.137 10.62 2.151 ;
     RECT  13.2 2.137 13.32 2.151 ;
     RECT  13.2 2.151 13.512 2.581 ;
     RECT  7.8 2.151 8.112 3.061 ;
     RECT  9.12 2.581 9.144 3.061 ;
     RECT  13.2 2.581 13.944 3.061 ;
     RECT  7.8 3.061 9.144 3.637 ;
     RECT  3.936 3.589 3.96 3.731 ;
     RECT  13.2 3.061 14.856 3.779 ;
     RECT  7.8 3.637 9.288 3.875 ;
     RECT  13.2 3.779 13.944 3.875 ;
     RECT  10.5 2.151 10.812 4.981 ;
     RECT  7.8 3.875 9.096 5.027 ;
     RECT  0.192 4.885 0.216 5.075 ;
     RECT  7.8 5.027 9 5.123 ;
     RECT  13.2 3.875 13.512 6.277 ;
     RECT  13.2 6.277 13.944 6.659 ;
     RECT  7.8 5.123 8.568 6.851 ;
     RECT  13.2 6.659 13.512 7.621 ;
     RECT  13.2 7.621 13.944 7.763 ;
     RECT  10.368 4.981 10.812 7.765 ;
     RECT  7.8 6.851 8.112 8.053 ;
     RECT  9.12 7.861 9.144 8.053 ;
     RECT  7.8 8.053 9.144 8.099 ;
     RECT  7.8 8.099 8.232 8.435 ;
     RECT  10.32 7.765 10.812 9.061 ;
     RECT  10.32 9.061 11.016 9.155 ;
     RECT  3.936 9.253 3.96 9.395 ;
     RECT  10.368 9.155 11.016 9.827 ;
     RECT  7.8 8.435 8.112 9.925 ;
     RECT  12.048 10.021 12.072 10.211 ;
     RECT  13.2 7.763 13.512 10.453 ;
     RECT  13.2 10.453 13.608 10.643 ;
     RECT  14.832 10.453 14.856 10.643 ;
     RECT  10.368 9.827 10.812 10.693 ;
     RECT  10.224 10.693 10.812 10.789 ;
     RECT  7.68 9.925 8.112 10.837 ;
     RECT  7.68 10.837 8.712 10.885 ;
     RECT  10.032 10.789 10.812 10.885 ;
     RECT  7.68 10.885 10.812 11.027 ;
     RECT  7.68 11.027 9 11.555 ;
     RECT  7.8 11.555 9 11.891 ;
     RECT  1.152 11.701 1.176 11.987 ;
     RECT  10.032 11.027 10.812 12.757 ;
     RECT  13.2 10.643 13.512 13.045 ;
     RECT  10.032 12.757 11.544 13.091 ;
     RECT  14.832 13.285 14.856 13.427 ;
     RECT  12.528 13.045 13.512 14.243 ;
     RECT  7.8 11.891 8.112 14.869 ;
     RECT  7.8 14.869 8.376 15.349 ;
     RECT  10.032 13.091 10.812 15.349 ;
     RECT  7.8 15.349 10.812 15.445 ;
     RECT  7.8 15.445 11.496 15.587 ;
     RECT  13.2 14.243 13.512 16.069 ;
     RECT  13.2 16.069 13.944 16.403 ;
     RECT  11.952 16.597 11.976 16.835 ;
     RECT  7.8 15.587 10.812 16.933 ;
     RECT  7.8 16.933 10.92 17.123 ;
     RECT  7.8 17.123 10.812 17.557 ;
     RECT  6.864 17.557 10.812 18.179 ;
     RECT  14.832 17.893 14.856 18.227 ;
     RECT  6.864 18.179 8.712 19.427 ;
     RECT  6.864 19.427 8.376 19.763 ;
     RECT  6.864 19.763 8.232 20.291 ;
     RECT  14.832 20.629 14.856 20.771 ;
     RECT  6.864 20.291 8.112 21.301 ;
     RECT  9.696 18.179 10.812 21.301 ;
     RECT  6.864 21.301 10.812 22.453 ;
     RECT  6.864 22.453 11.496 22.595 ;
     RECT  13.2 16.403 13.512 23.557 ;
     RECT  13.2 23.557 13.944 23.749 ;
     RECT  13.2 23.749 14.856 23.939 ;
     RECT  6.864 22.595 10.812 24.035 ;
     RECT  14.832 23.939 14.856 24.515 ;
     RECT  0.192 24.757 0.216 25.043 ;
     RECT  12 25.141 12.024 25.237 ;
     RECT  11.904 25.237 12.024 25.283 ;
     RECT  11.904 25.283 11.928 25.571 ;
     RECT  14.832 26.053 14.856 26.195 ;
     RECT  16.512 26.821 16.536 27.011 ;
     RECT  13.2 23.939 13.512 27.637 ;
     RECT  14.832 27.685 14.856 27.827 ;
     RECT  12.768 27.637 13.512 27.923 ;
     RECT  1.152 28.597 1.176 28.739 ;
     RECT  7.8 24.035 10.812 28.789 ;
     RECT  7.68 28.789 10.812 29.411 ;
     RECT  13.2 27.923 13.512 29.509 ;
     RECT  13.2 29.509 13.944 29.651 ;
     RECT  7.68 29.411 8.112 29.939 ;
     RECT  2.4 2.151 2.712 30.249 ;
     RECT  5.1 2.151 5.412 30.249 ;
     RECT  7.8 29.939 8.112 30.249 ;
     RECT  9.696 29.411 10.812 30.249 ;
     RECT  13.2 29.651 13.512 30.249 ;
     RECT  2.4 30.249 2.52 30.263 ;
     RECT  5.1 30.249 5.22 30.263 ;
     RECT  7.8 30.249 7.92 30.263 ;
     RECT  9.696 30.249 10.62 30.263 ;
     RECT  13.2 30.249 13.32 30.263 ;
     RECT  11.856 30.181 11.88 32.272 ;
     RECT  9.696 30.263 9.72 32.291 ;
  END
END dsfd_dvrly_276_EW
END LIBRARY
